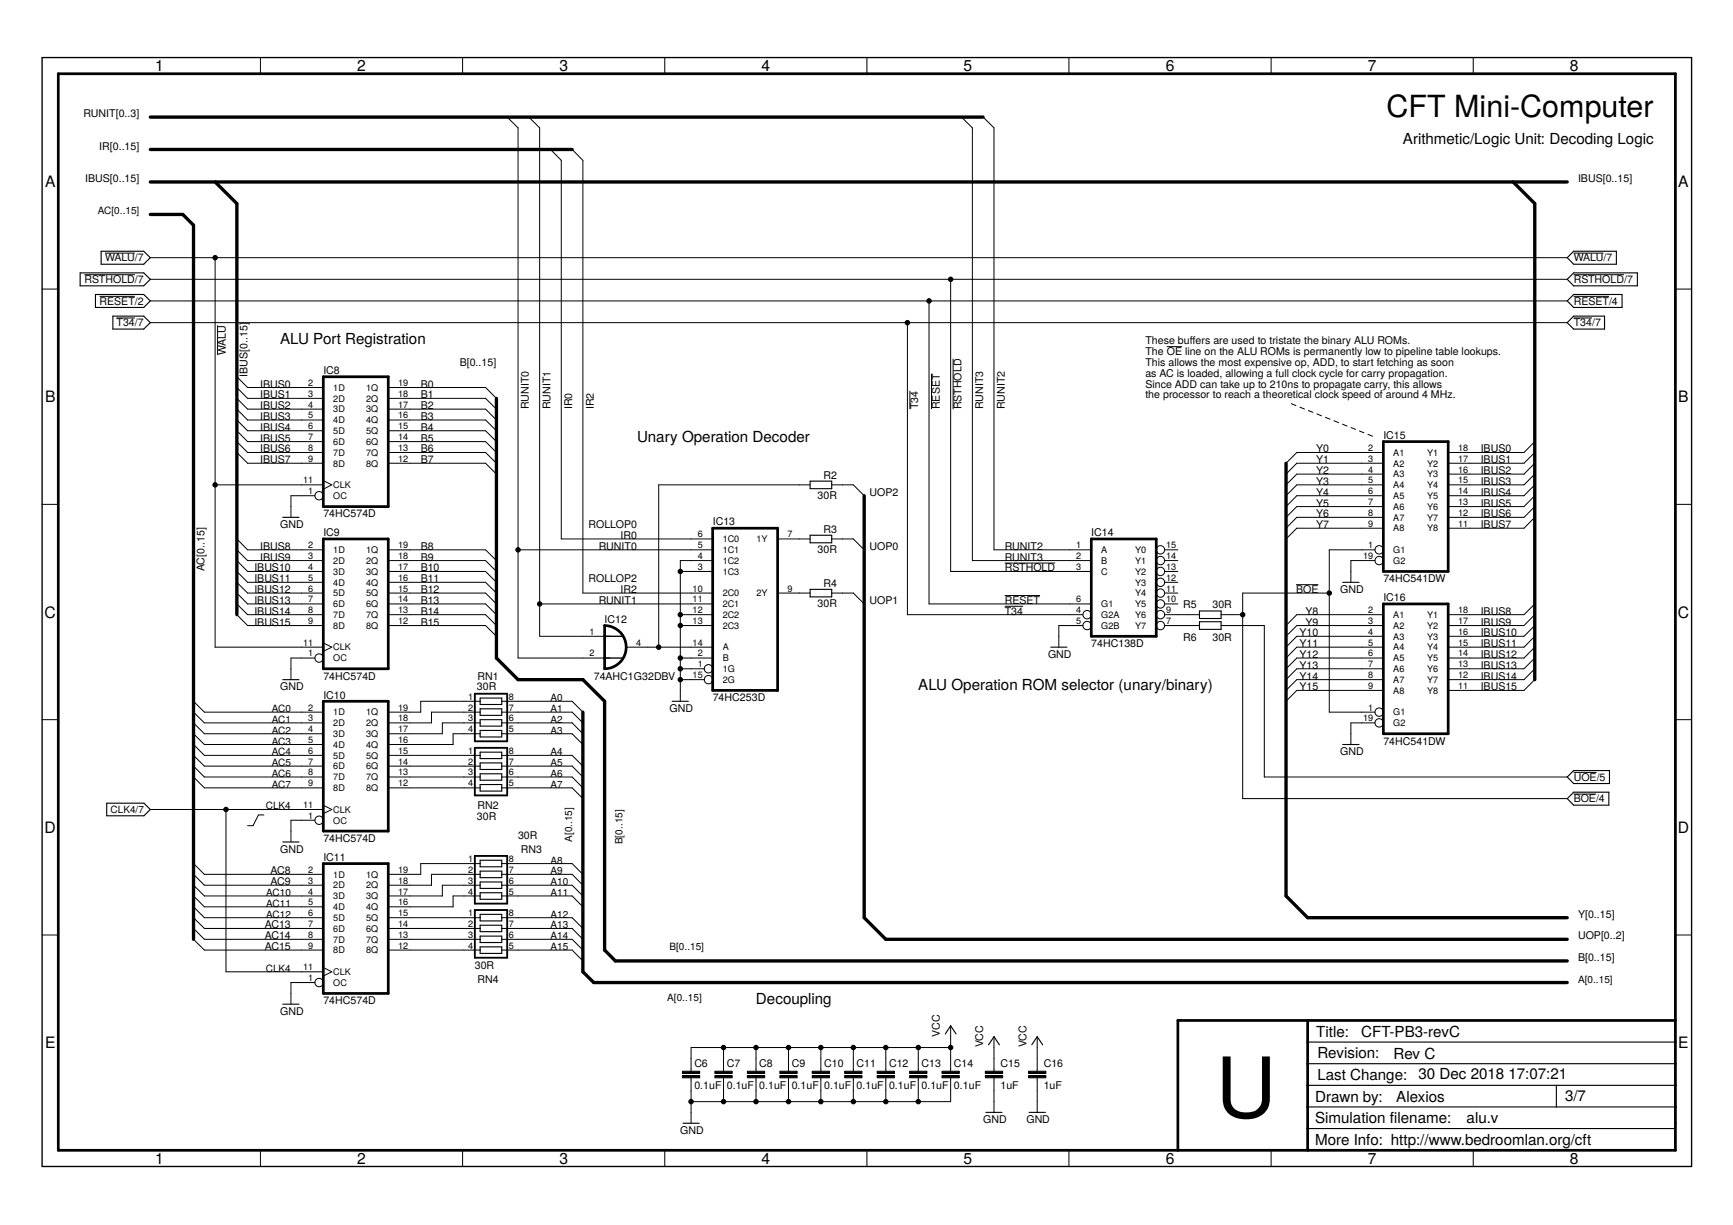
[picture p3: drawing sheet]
<svg xmlns="http://www.w3.org/2000/svg" width="297mm" height="210mm" viewBox="0 0 297 210" stroke-linecap="round" stroke-linejoin="round" font-family="sans-serif">
<defs><g id="words">
<text font-size="14.4" x="208.4" y="191.5">U</text>
<text font-size="5.2" x="237.6" y="20.1">CFT Mini-Computer</text>
<g font-size="2.7">
<text x="26.6" y="12.2">1</text>
<text x="61.2" y="12.2">2</text>
<text x="95.9" y="12.2">3</text>
<text x="130.5" y="12.2">4</text>
<text x="165.2" y="12.2">5</text>
<text x="199.8" y="12.2">6</text>
<text x="234.5" y="12.2">7</text>
<text x="269.1" y="12.2">8</text>
<text x="7.7" y="32">A</text>
<text x="287.7" y="32">A</text>
<text x="7.7" y="68.9">B</text>
<text x="287.7" y="68.9">B</text>
<text x="7.6" y="105.8">C</text>
<text x="287.6" y="105.8">C</text>
<text x="7.6" y="142.7">D</text>
<text x="287.6" y="142.7">D</text>
<text x="7.7" y="179.6">E</text>
<text x="287.7" y="179.6">E</text>
<text x="26.6" y="199.4">1</text>
<text x="61.2" y="199.4">2</text>
<text x="95.9" y="199.4">3</text>
<text x="130.5" y="199.4">4</text>
<text x="165.2" y="199.4">5</text>
<text x="199.8" y="199.4">6</text>
<text x="234.5" y="199.4">7</text>
<text x="269.1" y="199.4">8</text>
</g>
<g font-size="2.6">
<text x="240.5" y="24.7">Arithmetic/Logic Unit: Decoding Logic</text>
<text x="48" y="59">ALU Port Registration</text>
<text x="109.2" y="75.7">Unary Operation Decoder</text>
<text x="157.4" y="118.3">ALU Operation ROM selector (unary/binary)</text>
<text x="129.6" y="172.1">Decoupling</text>
<text x="225.6" y="177.6">Title:</text>
<text x="233.3" y="177.7">CFT-PB3-revC</text>
<text x="225.8" y="181.3">Revision:</text>
<text x="225.8" y="185">Last Change:</text>
<text x="238.9" y="181.4">Rev C</text>
<text x="243.1" y="185">30 Dec 2018</text>
<text x="258.6" y="185">17:07:21</text>
<text x="225.4" y="188.8">Drawn by:</text>
<text x="239.3" y="188.8">Alexios</text>
<text x="268.3" y="188.7">3/7</text>
<text x="225.4" y="192.5">Simulation flename:</text>
<text x="225.4" y="196.2">More Info: http://www.bedroomlan.org/cft</text>
<text x="238.2" y="192.5">i</text>
<text x="251.4" y="192.5">alu.v</text>
</g>
<g font-size="1.8">
<text x="14.3" y="20.1">RUNIT[0..3]</text>
<text x="17" y="25.6">IR[0..15]</text>
<text x="14.6" y="31.2">IBUS[0..15]</text>
<text x="270.5" y="31.2">IBUS[0..15]</text>
<text x="18" y="44.8">WALU/7</text>
<text x="269.7" y="44.8">WALU/7</text>
<text x="14.5" y="48.5">RSTHOLD/7</text>
<text x="17.1" y="52.2">RESET/2</text>
<text x="269.7" y="52.2">RESET/4</text>
<text x="269.7" y="48.5">RSTHOLD/7</text>
<text x="20" y="55.9">T34/7</text>
<text x="196.3" y="59">These bufers are used to tristate the binary ALU ROMs.</text>
<text x="203.9" y="59">f</text>
<text x="269.7" y="55.9">T34/7</text>
<text x="38.7" y="60.8" transform="rotate(-90 38.7 60.8)">WALU</text>
<text x="42.4" y="64.5" transform="rotate(-90 42.4 64.5)">IBUS[0..15]</text>
<text x="55.4" y="64.1">IC8</text>
<text x="78.8" y="62.7">B[0..15]</text>
<text x="196.3" y="60.8">The OE line on the ALU ROMs is permanently low to pipeline table lookups.</text>
<text x="196.3" y="62.7">This allows the most expensive op, ADD, to start fetching as soon</text>
<text x="196.3" y="64.5">as AC is loaded, allowing a full clock cycle for carry propagation.</text>
<text x="44.6" y="66.4">IBUS0</text>
<text x="44.6" y="68.3">IBUS1</text>
<text x="44.6" y="70.1">IBUS2</text>
<text x="44.6" y="72">IBUS3</text>
<text x="72.1" y="66.4">B0</text>
<text x="72.1" y="68.3">B1</text>
<text x="72.1" y="70.1">B2</text>
<text x="72.1" y="72">B3</text>
<text x="90.6" y="70.1" transform="rotate(-90 90.6 70.1)">RUNIT0</text>
<text x="94.4" y="70.1" transform="rotate(-90 94.4 70.1)">RUNIT1</text>
<text x="98.1" y="70.1" transform="rotate(-90 98.1 70.1)">IR0</text>
<text x="101.8" y="70.1" transform="rotate(-90 101.8 70.1)">IR2</text>
<text x="157.4" y="70.1" transform="rotate(-90 157.4 70.1)">T34</text>
<text x="161.1" y="70.1" transform="rotate(-90 161.1 70.1)">RESET</text>
<text x="164.8" y="70.1" transform="rotate(-90 164.8 70.1)">RSTHOLD</text>
<text x="168.5" y="70.1" transform="rotate(-90 168.5 70.1)">RUNIT3</text>
<text x="172.2" y="70.1" transform="rotate(-90 172.2 70.1)">RUNIT2</text>
<text x="196.3" y="66.4">Since ADD can take up to 210ns to propagate carry, this allows</text>
<text x="196.3" y="68.3">the processor to reach a theoretical clock speed of around 4 MHz.</text>
<text x="44.6" y="73.8">IBUS4</text>
<text x="44.6" y="75.7">IBUS5</text>
<text x="44.6" y="77.5">IBUS6</text>
<text x="72.1" y="73.8">B4</text>
<text x="72.1" y="75.7">B5</text>
<text x="72.1" y="77.5">B6</text>
<text x="225.6" y="77.5">Y0</text>
<text x="237.1" y="75.2">IC15</text>
<text x="253.8" y="77.5">IBUS0</text>
<text x="44.6" y="79.4">IBUS7</text>
<text x="72.1" y="79.4">B7</text>
<text x="141.2" y="82">R2</text>
<text x="225.6" y="79.4">Y1</text>
<text x="225.6" y="81.2">Y2</text>
<text x="225.6" y="83.1">Y3</text>
<text x="253.8" y="79.4">IBUS1</text>
<text x="253.8" y="81.2">IBUS2</text>
<text x="253.8" y="83.1">IBUS3</text>
<text x="55.4" y="88.6">74HC574D</text>
<text x="140.1" y="85.5">30R</text>
<text x="149" y="84.9">UOP2</text>
<text x="225.6" y="84.9">Y4</text>
<text x="225.6" y="86.8">Y5</text>
<text x="225.6" y="88.6">Y6</text>
<text x="253.8" y="84.9">IBUS4</text>
<text x="253.8" y="86.8">IBUS5</text>
<text x="253.8" y="88.6">IBUS6</text>
<text x="44.6" y="94.2">IBUS8</text>
<text x="48" y="90.5">GND</text>
<text x="55.4" y="91.9">IC9</text>
<text x="72.1" y="94.2">B8</text>
<text x="100.9" y="90.5">ROLLOP0</text>
<text x="102.6" y="94.2">RUNIT0</text>
<text x="106.3" y="92.4">IR0</text>
<text x="122.2" y="90">IC13</text>
<text x="140.1" y="94.8">30R</text>
<text x="141.2" y="91.3">R3</text>
<text x="149" y="94.2">UOP0</text>
<text x="172.2" y="94.2">RUNIT2</text>
<text x="187.1" y="91.9">IC14</text>
<text x="225.6" y="90.5">Y7</text>
<text x="253.8" y="90.5">IBUS7</text>
<text x="35" y="97.9" transform="rotate(-90 35 97.9)">AC[0..15]</text>
<text x="43.6" y="97.9">IBUS10</text>
<text x="43.6" y="99.8">IBUS11</text>
<text x="43.6" y="101.6">IBUS12</text>
<text x="44.6" y="96.1">IBUS9</text>
<text x="72.1" y="96.1">B9</text>
<text x="72.1" y="97.9">B10</text>
<text x="72.1" y="99.8">B11</text>
<text x="72.1" y="101.6">B12</text>
<text x="100.9" y="99.8">ROLLOP2</text>
<text x="106.3" y="101.6">IR2</text>
<text x="141.2" y="100.5">R4</text>
<text x="172.2" y="97.9">RSTHOLD</text>
<text x="172.2" y="96.1">RUNIT3</text>
<text x="222.2" y="101.6">BOE</text>
<text x="229.7" y="101.6">GND</text>
<text x="237.1" y="99.8">74HC541DW</text>
<text x="43.6" y="103.5">IBUS13</text>
<text x="43.6" y="105.3">IBUS14</text>
<text x="43.6" y="107.2">IBUS15</text>
<text x="72.1" y="103.5">B13</text>
<text x="72.1" y="105.3">B14</text>
<text x="72.1" y="107.2">B15</text>
<text x="102.6" y="103.5">RUNIT1</text>
<text x="103.6" y="106.7">IC12</text>
<text x="140.1" y="104">30R</text>
<text x="149" y="103.5">UOP1</text>
<text x="172.2" y="103.5">RESET</text>
<text x="172.2" y="105.3">T34</text>
<text x="202.8" y="104.2">R5</text>
<text x="207.8" y="104.2">30R</text>
<text x="223.8" y="105.3">Y8</text>
<text x="223.8" y="107.2">Y9</text>
<text x="237.1" y="103">IC16</text>
<text x="253.8" y="105.3">IBUS8</text>
<text x="253.8" y="107.2">IBUS9</text>
<text x="179.6" y="112.7">GND</text>
<text x="187.1" y="110.9">74HC138D</text>
<text x="202.8" y="109.8">R6</text>
<text x="207.8" y="109.8">30R</text>
<text x="222.7" y="109">Y10</text>
<text x="222.7" y="110.9">Y11</text>
<text x="222.7" y="112.7">Y12</text>
<text x="253.8" y="109">IBUS10</text>
<text x="253.8" y="110.9">IBUS11</text>
<text x="253.8" y="112.7">IBUS12</text>
<text x="48" y="118.3">GND</text>
<text x="55.4" y="116.5">74HC574D</text>
<text x="55.4" y="119.7">IC10</text>
<text x="81.7" y="118.3">30R</text>
<text x="81.8" y="116.5">RN1</text>
<text x="101.8" y="116.5">74AHC1G32DBV</text>
<text x="222.7" y="114.6">Y13</text>
<text x="222.7" y="116.5">Y14</text>
<text x="222.7" y="118.3">Y15</text>
<text x="253.8" y="114.6">IBUS13</text>
<text x="253.8" y="116.5">IBUS14</text>
<text x="253.8" y="118.3">IBUS15</text>
<text x="114.7" y="122">GND</text>
<text x="122.2" y="120.2">74HC253D</text>
<text x="229.7" y="129.4">GND</text>
<text x="237.1" y="127.6">74HC541DW</text>
<text x="269.7" y="133.8">UOE/5</text>
<text x="269.7" y="137.5">BOE/4</text>
<text x="81.7" y="140.5">30R</text>
<text x="81.8" y="138.7">RN2</text>
<text x="88.8" y="143.7">30R</text>
<text x="46.4" y="149.8">AC8</text>
<text x="48" y="146.1">GND</text>
<text x="55.4" y="144.3">74HC574D</text>
<text x="55.4" y="147.5">IC11</text>
<text x="89.3" y="146.1">RN3</text>
<text x="46.4" y="151.7">AC9</text>
<text x="45.4" y="159.1">AC13</text>
<text x="45.4" y="160.9">AC14</text>
<text x="270.5" y="160.9">UOP[0..2]</text>
<text x="270.5" y="157.2">Y[0..15]</text>
<text x="45.4" y="162.8">AC15</text>
<text x="81.4" y="166">30R</text>
<text x="270.5" y="164.7">B[0..15]</text>
<text x="48" y="173.9">GND</text>
<text x="55.4" y="172.1">74HC574D</text>
<text x="81.8" y="168.4">RN4</text>
<text x="161.1" y="177.6" transform="rotate(-90 161.1 177.6)">VCC</text>
<text x="168.5" y="179.5" transform="rotate(-90 168.5 179.5)">VCC</text>
<text x="175.9" y="179.5" transform="rotate(-90 175.9 179.5)">VCC</text>
<text x="119" y="182.9">C6</text>
<text x="124.6" y="182.9">C7</text>
<text x="130.1" y="182.9">C8</text>
<text x="135.7" y="182.9">C9</text>
<text x="141.3" y="182.9">C10</text>
<text x="146.8" y="182.9">C11</text>
<text x="152.4" y="182.9">C12</text>
<text x="157.9" y="182.9">C13</text>
<text x="163.5" y="182.9">C14</text>
<text x="171.5" y="182.9">C15</text>
<text x="178.9" y="182.9">C16</text>
<text x="119" y="186.6">0.1uF 0.1uF 0.1uF 0.1uF 0.1uF 0.1uF 0.1uF 0.1uF 0.1uF</text>
<text x="171.5" y="186.6">1uF</text>
<text x="178.9" y="186.6">1uF</text>
<text x="116.6" y="194.3">GND</text>
<text x="168.5" y="192.5">GND</text>
<text x="175.9" y="192.5">GND</text>
</g>
<g font-size="1.7">
<text x="16.8" y="36.7">AC[0..15]</text>
<text x="46.6" y="122">AC0</text>
<text x="46.6" y="123.9">AC1</text>
<text x="46.6" y="125.7">AC2</text>
<text x="94.4" y="125.7">A3</text>
<text x="94.4" y="123.9">A2</text>
<text x="94.4" y="122">A1</text>
<text x="94.4" y="120.2">A0</text>
<text x="46.6" y="127.6">AC3</text>
<text x="46.6" y="129.4">AC4</text>
<text x="46.6" y="131.3">AC5</text>
<text x="94.4" y="131.3">A5</text>
<text x="94.4" y="129.4">A4</text>
<text x="46.6" y="133.1">AC6</text>
<text x="46.6" y="135">AC7</text>
<text x="94.4" y="135">A7</text>
<text x="94.4" y="133.1">A6</text>
<text x="19" y="139.3">CLK4/7</text>
<text x="45.6" y="138.7">CLK4</text>
<text x="94.4" y="149.8">A9</text>
<text x="94.4" y="148">A8</text>
<text x="98.1" y="144.3" transform="rotate(-90 98.1 144.3)">A[0..15]</text>
<text x="106.7" y="144.6" transform="rotate(-90 106.7 144.6)">B[0..15]</text>
<text x="45.6" y="153.5">AC10</text>
<text x="45.6" y="155.4">AC11</text>
<text x="94.4" y="153.5">A11</text>
<text x="94.4" y="151.7">A10</text>
<text x="45.6" y="157.2">AC12</text>
<text x="94.4" y="160.9">A14</text>
<text x="94.4" y="159.1">A13</text>
<text x="94.4" y="157.2">A12</text>
<text x="45.6" y="166.5">CLK4</text>
<text x="94.4" y="162.8">A15</text>
<text x="114.7" y="162.8">B[0..15]</text>
<text x="114.4" y="171.4">A[0..15]</text>
<text x="270.5" y="168.4">A[0..15]</text>
</g>
<g font-size="1.6">
<text x="52.8" y="66.1">2</text>
<text x="52.8" y="68">3</text>
<text x="52.8" y="69.9">4</text>
<text x="52.8" y="71.7">5</text>
<text x="57.1" y="67">1D</text>
<text x="57.1" y="68.8">2D</text>
<text x="57.1" y="70.7">3D</text>
<text x="62.7" y="70.7">3Q</text>
<text x="62.7" y="68.8">2Q</text>
<text x="62.7" y="67">1Q</text>
<text x="68.2" y="71.7">16</text>
<text x="68.2" y="69.9">17</text>
<text x="68.2" y="68">18</text>
<text x="68.2" y="66.1">19</text>
<text x="52.8" y="73.6">6</text>
<text x="52.8" y="75.4">7</text>
<text x="52.8" y="77.3">8</text>
<text x="57.1" y="72.5">4D</text>
<text x="57.1" y="74.4">5D</text>
<text x="57.1" y="76.2">6D</text>
<text x="62.7" y="76.2">6Q</text>
<text x="62.7" y="74.4">5Q</text>
<text x="62.7" y="72.5">4Q</text>
<text x="68.2" y="77.3">13</text>
<text x="68.2" y="75.4">14</text>
<text x="68.2" y="73.6">15</text>
<text x="234.5" y="77.3">2</text>
<text x="249.9" y="77.3">18</text>
<text x="52" y="82.8">11</text>
<text x="52.8" y="79.1">9</text>
<text x="57.1" y="78.1">7D</text>
<text x="57.1" y="79.9">8D</text>
<text x="57.1" y="83.6">CLK</text>
<text x="62.7" y="79.9">8Q</text>
<text x="62.7" y="78.1">7Q</text>
<text x="68.2" y="79.1">12</text>
<text x="234.5" y="79.1">3</text>
<text x="234.5" y="81">4</text>
<text x="234.5" y="82.8">5</text>
<text x="238.8" y="78.1">A1</text>
<text x="238.8" y="79.9">A2</text>
<text x="238.8" y="81.8">A3</text>
<text x="238.8" y="83.6">A4</text>
<text x="244.6" y="83.7">Y4</text>
<text x="244.6" y="81.8">Y3</text>
<text x="244.6" y="79.9">Y2</text>
<text x="244.6" y="78.1">Y1</text>
<text x="249.9" y="82.8">15</text>
<text x="249.9" y="81">16</text>
<text x="249.9" y="79.1">17</text>
<text x="52.8" y="84.7">1</text>
<text x="57.1" y="85.5">OC</text>
<text x="234.5" y="84.7">6</text>
<text x="234.5" y="86.5">7</text>
<text x="234.5" y="88.4">8</text>
<text x="238.8" y="85.5">A5</text>
<text x="238.8" y="87.4">A6</text>
<text x="238.8" y="89.2">A7</text>
<text x="244.6" y="89.2">Y7</text>
<text x="244.6" y="87.4">Y6</text>
<text x="244.6" y="85.5">Y5</text>
<text x="249.9" y="88.4">12</text>
<text x="249.9" y="86.5">13</text>
<text x="249.9" y="84.7">14</text>
<text x="52.8" y="93.9">2</text>
<text x="52.8" y="95.8">3</text>
<text x="57.1" y="94.8">1D</text>
<text x="62.7" y="94.8">1Q</text>
<text x="68.2" y="95.8">18</text>
<text x="68.2" y="93.9">19</text>
<text x="119.6" y="95.8">4</text>
<text x="119.6" y="93.9">5</text>
<text x="119.6" y="92.1">6</text>
<text x="123.9" y="94.8">1C1</text>
<text x="123.9" y="92.9">1C0</text>
<text x="129.7" y="92.9">1Y</text>
<text x="135" y="92.1">7</text>
<text x="184.5" y="93.9">1</text>
<text x="184.5" y="95.8">2</text>
<text x="188.8" y="94.8">A</text>
<text x="194.6" y="94.8">Y0</text>
<text x="199.9" y="95.8">14</text>
<text x="199.9" y="93.9">15</text>
<text x="233.7" y="95.8">19</text>
<text x="234.5" y="93.9">1</text>
<text x="234.5" y="90.2">9</text>
<text x="238.8" y="94.8">G1</text>
<text x="238.8" y="91.1">A8</text>
<text x="244.6" y="91.1">Y8</text>
<text x="249.9" y="90.2">11</text>
<text x="52.8" y="97.7">4</text>
<text x="52.8" y="99.5">5</text>
<text x="52.8" y="101.4">6</text>
<text x="57.1" y="96.6">2D</text>
<text x="57.1" y="98.5">3D</text>
<text x="57.1" y="100.3">4D</text>
<text x="62.7" y="100.3">4Q</text>
<text x="62.7" y="98.5">3Q</text>
<text x="62.7" y="96.6">2Q</text>
<text x="68.2" y="101.4">15</text>
<text x="68.2" y="99.5">16</text>
<text x="68.2" y="97.7">17</text>
<text x="118.7" y="101.4">10</text>
<text x="119.6" y="97.7">3</text>
<text x="123.9" y="98.5">1C3</text>
<text x="123.9" y="96.6">1C2</text>
<text x="135" y="101.4">9</text>
<text x="184.5" y="97.7">3</text>
<text x="188.8" y="96.6">B</text>
<text x="188.8" y="98.5">C</text>
<text x="194.6" y="100.3">Y3</text>
<text x="194.6" y="98.5">Y2</text>
<text x="194.6" y="96.6">Y1</text>
<text x="199.9" y="101.4">11</text>
<text x="199.9" y="99.5">12</text>
<text x="199.9" y="97.7">13</text>
<text x="238.8" y="96.6">G2</text>
<text x="52.8" y="103.2">7</text>
<text x="52.8" y="105.1">8</text>
<text x="52.8" y="106.9">9</text>
<text x="57.1" y="102.2">5D</text>
<text x="57.1" y="104">6D</text>
<text x="57.1" y="105.9">7D</text>
<text x="57.1" y="107.7">8D</text>
<text x="62.7" y="107.8">8Q</text>
<text x="62.7" y="105.9">7Q</text>
<text x="62.7" y="104">6Q</text>
<text x="62.7" y="102.2">5Q</text>
<text x="68.2" y="106.9">12</text>
<text x="68.2" y="105.1">13</text>
<text x="68.2" y="103.2">14</text>
<text x="118.7" y="103.2">11</text>
<text x="118.7" y="105.1">12</text>
<text x="118.7" y="106.9">13</text>
<text x="123.9" y="102.2">2C0</text>
<text x="123.9" y="104">2C1</text>
<text x="123.9" y="105.9">2C2</text>
<text x="123.9" y="107.7">2C3</text>
<text x="129.7" y="102.2">2Y</text>
<text x="184.5" y="105.1">4</text>
<text x="184.5" y="106.9">5</text>
<text x="184.5" y="103.2">6</text>
<text x="188.8" y="105.9">G2A</text>
<text x="188.8" y="107.7">G2B</text>
<text x="188.8" y="104">G1</text>
<text x="194.6" y="107.8">Y7</text>
<text x="194.6" y="105.9">Y6</text>
<text x="194.6" y="104">Y5</text>
<text x="194.6" y="102.2">Y4</text>
<text x="199.9" y="106.9">7</text>
<text x="199.9" y="105.1">9</text>
<text x="199.9" y="103.2">10</text>
<text x="234.5" y="105.1">2</text>
<text x="234.5" y="106.9">3</text>
<text x="238.8" y="105.9">A1</text>
<text x="238.8" y="107.7">A2</text>
<text x="244.6" y="107.8">Y2</text>
<text x="244.6" y="105.9">Y1</text>
<text x="249.9" y="106.9">17</text>
<text x="249.9" y="105.1">18</text>
<text x="52" y="110.6">11</text>
<text x="52.8" y="112.5">1</text>
<text x="57.1" y="113.3">OC</text>
<text x="57.1" y="111.4">CLK</text>
<text x="101" y="108.8">1</text>
<text x="101" y="112.5">2</text>
<text x="109" y="110.6">4</text>
<text x="118.7" y="110.6">14</text>
<text x="119.6" y="112.5">2</text>
<text x="123.9" y="113.3">B</text>
<text x="123.9" y="111.4">A</text>
<text x="234.5" y="108.8">4</text>
<text x="234.5" y="110.6">5</text>
<text x="234.5" y="112.5">6</text>
<text x="238.8" y="109.6">A3</text>
<text x="238.8" y="111.4">A4</text>
<text x="238.8" y="113.3">A5</text>
<text x="244.6" y="113.3">Y5</text>
<text x="244.6" y="111.5">Y4</text>
<text x="244.6" y="109.6">Y3</text>
<text x="249.9" y="112.5">14</text>
<text x="249.9" y="110.6">15</text>
<text x="249.9" y="108.8">16</text>
<text x="80.2" y="119.9">1</text>
<text x="87.2" y="119.9">8</text>
<text x="118.7" y="116.2">15</text>
<text x="119.6" y="114.3">1</text>
<text x="123.9" y="115.2">1G</text>
<text x="123.9" y="117">2G</text>
<text x="234.5" y="114.3">7</text>
<text x="234.5" y="116.2">8</text>
<text x="234.5" y="118">9</text>
<text x="238.8" y="115.2">A6</text>
<text x="238.8" y="117">A7</text>
<text x="238.8" y="118.9">A8</text>
<text x="244.6" y="118.9">Y8</text>
<text x="244.6" y="117">Y7</text>
<text x="244.6" y="115.2">Y6</text>
<text x="249.9" y="118">11</text>
<text x="249.9" y="116.2">12</text>
<text x="249.9" y="114.3">13</text>
<text x="52.8" y="121.8">2</text>
<text x="52.8" y="123.6">3</text>
<text x="52.8" y="125.5">4</text>
<text x="57.1" y="122.6">1D</text>
<text x="57.1" y="124.4">2D</text>
<text x="62.7" y="124.4">2Q</text>
<text x="62.7" y="122.6">1Q</text>
<text x="68.2" y="125.5">17</text>
<text x="68.2" y="123.6">18</text>
<text x="68.2" y="121.8">19</text>
<text x="80.2" y="121.8">2</text>
<text x="80.2" y="123.6">3</text>
<text x="80.2" y="125.5">4</text>
<text x="87.2" y="125.5">5</text>
<text x="87.2" y="123.6">6</text>
<text x="87.2" y="121.8">7</text>
<text x="233.7" y="123.6">19</text>
<text x="234.5" y="121.8">1</text>
<text x="238.8" y="122.6">G1</text>
<text x="238.8" y="124.4">G2</text>
<text x="52.8" y="127.3">5</text>
<text x="52.8" y="129.2">6</text>
<text x="52.8" y="131">7</text>
<text x="57.1" y="126.3">3D</text>
<text x="57.1" y="128.1">4D</text>
<text x="57.1" y="130">5D</text>
<text x="57.1" y="131.8">6D</text>
<text x="62.7" y="131.9">6Q</text>
<text x="62.7" y="130">5Q</text>
<text x="62.7" y="128.1">4Q</text>
<text x="62.7" y="126.3">3Q</text>
<text x="68.2" y="131">14</text>
<text x="68.2" y="129.2">15</text>
<text x="68.2" y="127.3">16</text>
<text x="80.2" y="131">2</text>
<text x="80.2" y="129.2">1</text>
<text x="87.2" y="131">7</text>
<text x="87.2" y="129.2">8</text>
<text x="52.8" y="132.9">8</text>
<text x="52.8" y="134.7">9</text>
<text x="57.1" y="133.7">7D</text>
<text x="57.1" y="135.5">8D</text>
<text x="62.7" y="135.6">8Q</text>
<text x="62.7" y="133.7">7Q</text>
<text x="68.2" y="134.7">12</text>
<text x="68.2" y="132.9">13</text>
<text x="80.2" y="132.9">3</text>
<text x="80.2" y="134.7">4</text>
<text x="87.2" y="134.7">5</text>
<text x="87.2" y="132.9">6</text>
<text x="52" y="138.4">11</text>
<text x="52.8" y="140.3">1</text>
<text x="57.1" y="141.1">OC</text>
<text x="57.1" y="139.3">CLK</text>
<text x="52.8" y="149.6">2</text>
<text x="68.2" y="149.6">19</text>
<text x="80.2" y="149.6">2</text>
<text x="80.2" y="147.7">1</text>
<text x="87.2" y="149.6">7</text>
<text x="87.2" y="147.7">8</text>
<text x="52.8" y="151.4">3</text>
<text x="52.8" y="153.3">4</text>
<text x="52.8" y="155.1">5</text>
<text x="57.1" y="150.4">1D</text>
<text x="57.1" y="152.2">2D</text>
<text x="57.1" y="154.1">3D</text>
<text x="57.1" y="155.9">4D</text>
<text x="62.7" y="156">4Q</text>
<text x="62.7" y="154.1">3Q</text>
<text x="62.7" y="152.2">2Q</text>
<text x="62.7" y="150.4">1Q</text>
<text x="68.2" y="155.1">16</text>
<text x="68.2" y="153.3">17</text>
<text x="68.2" y="151.4">18</text>
<text x="80.2" y="151.4">3</text>
<text x="80.2" y="153.3">4</text>
<text x="87.2" y="153.3">5</text>
<text x="87.2" y="151.4">6</text>
<text x="52.8" y="157">6</text>
<text x="52.8" y="158.8">7</text>
<text x="52.8" y="160.7">8</text>
<text x="57.1" y="157.8">5D</text>
<text x="57.1" y="159.6">6D</text>
<text x="57.1" y="161.5">7D</text>
<text x="62.7" y="161.5">7Q</text>
<text x="62.7" y="159.7">6Q</text>
<text x="62.7" y="157.8">5Q</text>
<text x="68.2" y="160.7">13</text>
<text x="68.2" y="158.8">14</text>
<text x="68.2" y="157">15</text>
<text x="80.2" y="158.8">2</text>
<text x="80.2" y="160.7">3</text>
<text x="80.2" y="157">1</text>
<text x="87.2" y="160.7">6</text>
<text x="87.2" y="158.8">7</text>
<text x="87.2" y="157">8</text>
<text x="52" y="166.2">11</text>
<text x="52.8" y="162.5">9</text>
<text x="57.1" y="163.4">8D</text>
<text x="57.1" y="167.1">CLK</text>
<text x="62.7" y="163.4">8Q</text>
<text x="68.2" y="162.5">12</text>
<text x="80.2" y="162.5">4</text>
<text x="87.2" y="162.5">5</text>
<text x="52.8" y="168.1">1</text>
<text x="57.1" y="168.9">OC</text>
</g>
</g></defs>
<g fill="none" stroke="#000" stroke-width=".17">
<path d="M10 12.6h277.2v184.5h-277.2zM44.6 9.9v2.7M79.3 9.9v2.7M113.9 9.9v2.7M148.6 9.9v2.7M183.2 9.9v2.7M217.9 9.9v2.7M252.5 9.9v2.7M86.9 20.1l1.9 1.8v90.9h15.7M90.6 20.1l1.9 1.8v87.1h12M94.4 25.6l1.8 1.9v64.9h26M98.1 25.6l1.8 1.9v74.1h22.3"/>
<path d="M164.8 20.1l1.9 1.8v74.2h20.3M168.5 20.1l1.9 1.8v72.3h16.6M7.2 49.5h2.8M14.5 47.1h8.6M17.1 50.8h6M18 43.4h5.1M20 54.5h3.1M25.8 51.6h242.8M25.8 47.9h242.8M25.8 44.2h242.8M25.8 55.3h242.8M36.9 44.2v66.7h18.5"/>
<path d="M37.3 55.7v5.1M155.5 55.3v50h30.1M159.2 51.6v51.9h27.8M162.9 47.9v50h24.1M200 59.4h2.6M269.7 50.8h6.1M269.7 47.1h8.7M269.7 43.4h5.1M269.7 54.5h3.2M287.2 49.5h2.7M40.6 64.6l1.8 1.8h13M40.6 66.4l1.8 1.9h13"/>
<path d="M40.6 68.3l1.8 1.8h13M40.6 70.1l1.8 1.9h13M40.6 72l1.8 1.8h13M40.6 73.8l1.8 1.9h13M40.6 75.7l1.8 1.8h13M40.6 77.5l1.8 1.9h13M66.5 66.4h16.7l1.9 1.9M66.5 68.3h16.7l1.9 1.8M66.5 70.1h16.7l1.9 1.9M66.5 72h16.7l1.9 1.8M66.5 73.8h16.7l1.9 1.9M66.5 75.7h16.7l1.9 1.8"/>
<path d="M66.5 77.5h16.7l1.9 1.9M66.5 79.4h16.7l1.9 1.8M156 67v3.1M159.7 64.1v6M163.4 61.5v8.6M221.3 69.2l.8 .3M222.8 69.8l.8 .3M224.3 70.4l.7 .3M225.7 70.9l.8 .3M227.2 71.5l.8 .3M228.6 72.1l.8 .3M230.1 72.7l.8 .3"/>
<path d="M231.6 73.3l.7 .3M233 73.9l.8 .3M234.5 74.4l.7 .3M237.1 77.5h-14.8l-1.9 1.9M237.1 79.4h-14.8l-1.9 1.8M263.1 75.7l-1.9 1.8h-13M263.1 77.5l-1.9 1.9h-13M263.1 79.4l-1.9 1.8h-13M7.2 86.4h2.8M36.9 83.1h18.5M40.6 92.4l1.8 1.8h13M40.6 94.2l1.8 1.9h13"/>
<path d="M40.6 96.1l1.8 1.8h13M40.6 99.8l1.8 1.8h13M40.6 97.9l1.8 1.9h13M54 84.9h-4.1v3.7M55.4 82.4l1.5 .7-1.5 .7M66.5 94.2h16.7l1.9 1.9M66.5 96.1h16.7l1.9 1.8M66.5 97.9h16.7l1.9 1.9M66.5 99.8h16.7l1.9 1.8M88.8 94.2h33.4M116.6 97.9h5.6M122.2 96.1h-5.6v24.1"/>
<path d="M133.3 92.4h5.6M138.9 83.1h-26v27.8M142.6 83.1h3.7l1.8 1.8M142.6 92.4h3.7l1.8 1.8M172.2 96.5h8.6M199.6 94.2h2.3M199.6 96.1h2.3M199.6 97.9h2.3M199.6 99.8h2.3M235.7 94.2h-7.9v27.8h7.9M235.7 96.1h-4.2v3.7M237.1 84.9h-14.8l-1.9 1.9"/>
<path d="M237.1 83.1h-14.8l-1.9 1.8M237.1 81.2h-14.8l-1.9 1.9M237.1 86.8h-14.8l-1.9 1.8M237.1 88.6h-14.8l-1.9 1.9M237.1 90.5h-14.8l-1.9 1.9M263.1 83.1l-1.9 1.8h-13M263.1 81.2l-1.9 1.9h-13M263.1 84.9l-1.9 1.9h-13M263.1 86.8l-1.9 1.8h-13M263.1 88.6l-1.9 1.9h-13M287.2 86.4h2.7M40.6 103.5l1.8 1.8h13"/>
<path d="M40.6 105.3l1.8 1.9h13M40.6 101.6l1.8 1.9h13M54 112.8h-4.1v3.7M55.4 110.2l1.5 .7-1.5 .7M66.5 105.3h16.7l1.9 1.9M66.5 107.2h16.7l1.9 1.8M66.5 103.5h16.7l1.9 1.8M66.5 101.6h16.7l1.9 1.9M92.5 103.5h29.7M107.3 110.9h14.9M116.6 105.3h5.6M116.6 107.2h5.6"/>
<path d="M116.6 114.6h4.1M116.6 112.8h5.6M116.6 116.5h4.1M133.3 101.6h5.6M142.6 101.6h3.7l1.8 1.9M172.2 102h6.1M172.2 103.9h3.2M185.6 107.2h-4.1v3.7M199.6 105.3h6M199.6 107.2h6M199.6 103.5h2.3M199.6 101.6h2.3"/>
<path d="M209.3 105.3h3.7M209.3 107.2h7.4v25.9h51.9M222.1 100.2h3.9M227.8 101.6h-14.8v35.2h55.6M237.1 105.3h-14.8l-1.9 1.9M237.1 107.2h-14.8l-1.9 1.8M237.1 114.6h-14.8l-1.9 1.9M237.1 112.8h-14.8l-1.9 1.8M237.1 110.9h-14.8l-1.9 1.9M237.1 116.5h-14.8l-1.9 1.8M237.1 109h-14.8l-1.9 1.9M237.1 118.3h-14.8l-1.9 1.9"/>
<path d="M263.1 103.5l-1.9 1.8h-13M263.1 105.3l-1.9 1.9h-13M263.1 112.8l-1.9 1.8h-13M263.1 110.9l-1.9 1.9h-13M263.1 109l-1.9 1.9h-13M263.1 114.6l-1.9 1.9h-13M263.1 107.2l-1.9 1.8h-13M263.1 116.5l-1.9 1.8h-13M7.2 123.3h2.8M25.8 138.7h29.6M33.2 120.2l1.8 1.8h20.4M33.2 122l1.8 1.9h20.4"/>
<path d="M33.2 123.9l1.8 1.8h20.4M33.2 125.7l1.8 1.9h20.4M33.2 127.6l1.8 1.8h20.4M33.2 129.4l1.8 1.9h20.4M33.2 131.3l1.8 1.8h20.4M33.2 133.1l1.8 1.9h20.4M38.7 138.7v27.8h16.7M45.2 139.6h-.9l-.9 1.9h-1M55.4 138l1.5 .7-1.5 .7M66.5 129.4h15.8M66.5 131.3h15.8M66.5 133.1h15.8"/>
<path d="M66.5 135h15.8M82.3 120.2h-10.2v1.8h-5.6M82.3 122h-8.3v1.9h-7.5M82.3 123.9h-6.5v1.8h-9.3M82.3 125.7h-4.6v1.9h-11.2M86 122h12.1l1.8 1.9M86 123.9h12.1l1.8 1.8M86 125.7h12.1l1.8 1.9M86 129.4h12.1l1.8 1.9M86 131.3h12.1l1.8 1.8M86 133.1h12.1l1.8 1.9M86 135h12.1l1.8 1.8"/>
<path d="M86 120.2h12.1l1.8 1.8M235.7 123.9h-4.2v3.7M269.7 132.4h4M269.7 136.1h3.9M287.2 123.3h2.7M33.2 148l1.8 1.8h20.4M33.2 149.8l1.8 1.9h20.4M33.2 151.7l1.8 1.8h20.4M33.2 153.5l1.8 1.9h20.4M33.2 155.4l1.8 1.8h20.4M33.2 157.2l1.8 1.9h20.4M33.2 159.1l1.8 1.9h20.4"/>
<path d="M54 140.5h-4.1v3.8M66.5 157.2h15.8M66.5 159.1h15.8M82.3 148h-10.2v1.8h-5.6M82.3 149.8h-8.3v1.9h-7.5M82.3 151.7h-6.5v1.8h-9.3M82.3 153.5h-4.6v1.9h-11.2M86 149.8h12.1l1.8 1.9M86 151.7h12.1l1.8 1.8M86 153.5h12.1l1.8 1.9M86 157.2h12.1l1.8 1.9M86 159.1h12.1l1.8 1.9"/>
<path d="M86 148h12.1l1.8 1.8M7.2 160.2h2.8M33.2 161l1.8 1.8h20.4M54 168.4h-4.1v3.7M55.4 165.8l1.5 .7-1.5 .7M66.5 161h15.8M66.5 162.8h15.8M86 161h12.1l1.8 1.8M86 162.8h12.1l1.8 1.9M124 179.5v4.1M129.6 179.5v4.1M135.1 179.5v4.1"/>
<path d="M140.7 179.5v4.1M146.3 179.5v4.1M151.8 179.5v4.1M157.4 179.5v4.1M162.9 175.8v7.8M162.9 179.5h-44.5v4.1M170.4 177.6v6M177.8 177.6v6M287.2 160.2h2.7M44.6 197.1v2.8M79.3 197.1v2.8M113.9 197.1v2.8"/>
<path d="M118.4 184.7v7.8M124 184.7v4.1M129.6 184.7v4.1M135.1 184.7v4.1M140.7 184.7v4.1M146.3 184.7v4.1M148.6 197.1v2.8M151.8 184.7v4.1M157.4 184.7v4.1M162.9 184.7v4.1h-44.5M170.4 184.7v5.9M177.8 184.7v5.9"/>
<path d="M183.2 197.1v2.8M217.9 197.1v2.8M252.5 197.1v2.8M287.2 197h.1"/>
<circle cx="54.7" cy="84.9" r=".72"/>
<circle cx="198.9" cy="96.1" r=".72"/>
<circle cx="198.9" cy="99.8" r=".72"/>
<circle cx="198.9" cy="94.2" r=".72"/>
<circle cx="198.9" cy="97.9" r=".72"/>
<circle cx="236.4" cy="94.2" r=".72"/>
<circle cx="236.4" cy="96.1" r=".72"/>
<circle cx="54.7" cy="112.8" r=".72"/>
<circle cx="121.4" cy="114.6" r=".72"/>
<circle cx="121.4" cy="116.5" r=".72"/>
<circle cx="186.3" cy="105.3" r=".72"/>
<circle cx="186.3" cy="107.2" r=".72"/>
<circle cx="198.9" cy="101.6" r=".72"/>
<circle cx="198.9" cy="103.5" r=".72"/>
<circle cx="198.9" cy="107.2" r=".72"/>
<circle cx="198.9" cy="105.3" r=".72"/>
<circle cx="236.4" cy="123.9" r=".72"/>
<circle cx="236.4" cy="122" r=".72"/>
<circle cx="54.7" cy="140.5" r=".72"/>
<circle cx="54.7" cy="168.4" r=".72"/>
</g>
<g fill="none" stroke="#000" stroke-width=".19">
<path d="M13.7 46.8h10.9l1.2 1.1-1.2 1.1h-10.9zM16.4 50.5h8.2l1.2 1.1-1.2 1.1h-8.2zM17.3 43.1h7.3l1.2 1.1-1.2 1.1h-7.3zM19.3 54.2h5.3l1.2 1.1-1.2 1.1h-5.3zM268.6 51.6l1.1-1.1h8.3v2.2h-8.3zM268.6 44.2l1.1-1.1h7.4v2.2h-7.4zM269.7 46.8h10.9v2.2h-10.9l-1.1-1.1zM269.7 54.2h5.3v2.2h-5.3l-1.1-1.1zM48.5 88.6h2.7M138.9 82.4h3.7v1.3h-3.7zM138.9 91.7h3.7v1.3h-3.7zM230.1 99.8h2.8"/>
<path d="M48.5 116.5h2.7M82.3 119.6h3.7v1.1h-3.7zM138.9 101h3.7v1.3h-3.7zM180.1 110.9h2.8M205.6 104.7h3.7v1.3h-3.7zM205.6 106.5h3.7v1.3h-3.7zM18.3 137.6h6.4l1.1 1.1-1.1 1.1h-6.4zM82.3 121.5h3.7v1.1h-3.7zM82.3 123.3h3.7v1.1h-3.7zM82.3 125.2h3.7v1.1h-3.7zM82.3 128.9h3.7v1.1h-3.7zM82.3 130.7h3.7v1.1h-3.7z"/>
<path d="M82.3 132.6h3.7v1.1h-3.7zM82.3 134.4h3.7v1.2h-3.7zM115.2 120.2h2.8M230.1 127.6h2.8M268.6 133.1l1.1-1.1h6.2v2.3h-6.2zM269.7 135.7h6.1v2.3h-6.1l-1.1-1.2zM48.5 144.3h2.7M82.3 147.4h3.7v1.1h-3.7zM82.3 149.3h3.7v1.1h-3.7zM82.3 151.1h3.7v1.1h-3.7zM82.3 153h3.7v1.1h-3.7zM82.3 156.7h3.7v1.1h-3.7z"/>
<path d="M82.3 158.5h3.7v1.1h-3.7zM48.5 172.1h2.7M82.3 160.4h3.7v1.1h-3.7zM82.3 162.2h3.7v1.2h-3.7zM162 177.2l.9-1.4 1 1.4M169.4 179l1-1.4 .9 1.4M176.8 179l1-1.4 .9 1.4M224.1 178.6h63.1M117.1 192.5h2.7M169 190.6h2.7M176.4 190.6h2.8M224.1 182.3h63.1"/>
<path d="M224.1 186h63.1M224.1 189.7h63.1M266.8 186v3.7M287.2 192.5v.9h-63.1"/>
</g>
<path d="M10 12.6h277.2v184.5h-277.2zM55.4 64.6h11.1v22.2h-11.1zM237.1 75.7h11.1v22.2h-11.1zM55.4 92.4h11.1v22.2h-11.1zM122.2 90.5h11.1v27.8h-11.1zM187 92.4h11.2v16.6h-11.2zM103.6 107.2a3.7 3.7 0 0 1 3.7 3.7 3.7 3.7 0 0 1-3.7 3.7zM237.1 103.5h11.1v22.2h-11.1zM55.4 120.2h11.1v22.2h-11.1zM55.4 148h11.1v22.2h-11.1zM224.1 174.9v22.2M287.2 174.9h-85.3v22.2" fill="none" stroke="#000" stroke-width=".47"/>
<path d="M7.2 9.9h282.7v190h-282.7zM103.6 109h3.2M103.6 112.8h3.2" fill="none" stroke="#000" stroke-width=".23"/>
<g fill="#000" stroke="#000" stroke-width=".17">
<path d="M117 183.6h2.9v.3h-2.9zM117 184.3h2.9v.4h-2.9zM122.5 183.6h3v.3h-3zM122.5 184.3h3v.4h-3zM128.1 183.6h3v.3h-3zM128.1 184.3h3v.4h-3zM133.7 183.6h2.9v.3h-2.9zM133.7 184.3h2.9v.4h-2.9zM139.2 183.6h3v.3h-3zM139.2 184.3h3v.4h-3zM144.8 183.6h2.9v.3h-2.9zM144.8 184.3h2.9v.4h-2.9z"/>
<path d="M150.3 183.6h3v.3h-3zM150.3 184.3h3v.4h-3zM155.9 183.6h3v.3h-3zM155.9 184.3h3v.4h-3zM161.5 183.6h2.9v.3h-2.9zM161.5 184.3h2.9v.4h-2.9zM168.9 184.3h3v.4h-3zM168.9 183.6h3v.3h-3zM176.3 184.3h3v.4h-3zM176.3 183.6h3v.3h-3z"/>
</g>
<path d="M81.4 118.9h5.5v8.1h-5.5zM81.4 128.1h5.5v8.2h-5.5zM81.4 146.7h5.5v8.1h-5.5zM81.4 155.9h5.5v8.2h-5.5z" fill="none" stroke="#000" stroke-width=".32"/>
<path d="M25.8 31.2h242.8M25.8 25.6h72.3M25.8 20.1h142.7M25.8 36.7h5.5l1.9 1.9v122.4M36.9 31.2l3.7 3.7v70.4M259.4 31.2l3.7 3.7v81.6M85.1 68.3v44.5l3.7 3.7h11.1l3.7 3.7v42.6l1.9 1.9h163.1M220.4 79.4v74.1l3.7 3.7h44.5M148.1 84.9v72.3l3.7 3.8h116.8M99.9 122v44.5l1.9 1.9h166.8" fill="none" stroke="#000" stroke-width=".57"/>
<g fill="#000" stroke="#000" stroke-width=".17">
<circle cx="36.9" cy="44.2" r=".38"/>
<circle cx="155.5" cy="55.3" r=".38"/>
<circle cx="159.2" cy="51.6" r=".38"/>
<circle cx="162.9" cy="47.9" r=".38"/>
<circle cx="36.9" cy="83.1" r=".38"/>
<circle cx="88.8" cy="94.2" r=".38"/>
<circle cx="116.6" cy="97.9" r=".38"/>
<circle cx="92.5" cy="103.5" r=".38"/>
<circle cx="112.9" cy="110.9" r=".38"/>
<circle cx="116.6" cy="105.3" r=".38"/>
<circle cx="116.6" cy="107.2" r=".38"/>
<circle cx="116.6" cy="112.8" r=".38"/>
<circle cx="116.6" cy="114.6" r=".38"/>
<circle cx="116.6" cy="116.5" r=".38"/>
<circle cx="213" cy="105.3" r=".38"/>
<circle cx="227.8" cy="101.6" r=".38"/>
<circle cx="38.7" cy="138.7" r=".38"/>
<circle cx="124" cy="179.5" r=".38"/>
<circle cx="129.6" cy="179.5" r=".38"/>
<circle cx="135.1" cy="179.5" r=".38"/>
<circle cx="140.7" cy="179.5" r=".38"/>
<circle cx="146.3" cy="179.5" r=".38"/>
<circle cx="151.8" cy="179.5" r=".38"/>
<circle cx="157.4" cy="179.5" r=".38"/>
<circle cx="162.9" cy="179.5" r=".38"/>
<circle cx="118.4" cy="188.8" r=".38"/>
<circle cx="124" cy="188.8" r=".38"/>
<circle cx="129.6" cy="188.8" r=".38"/>
<circle cx="135.1" cy="188.8" r=".38"/>
<circle cx="140.7" cy="188.8" r=".38"/>
<circle cx="146.3" cy="188.8" r=".38"/>
<circle cx="151.8" cy="188.8" r=".38"/>
<circle cx="157.4" cy="188.8" r=".38"/>
</g>
<use href="#words"/>
</svg>
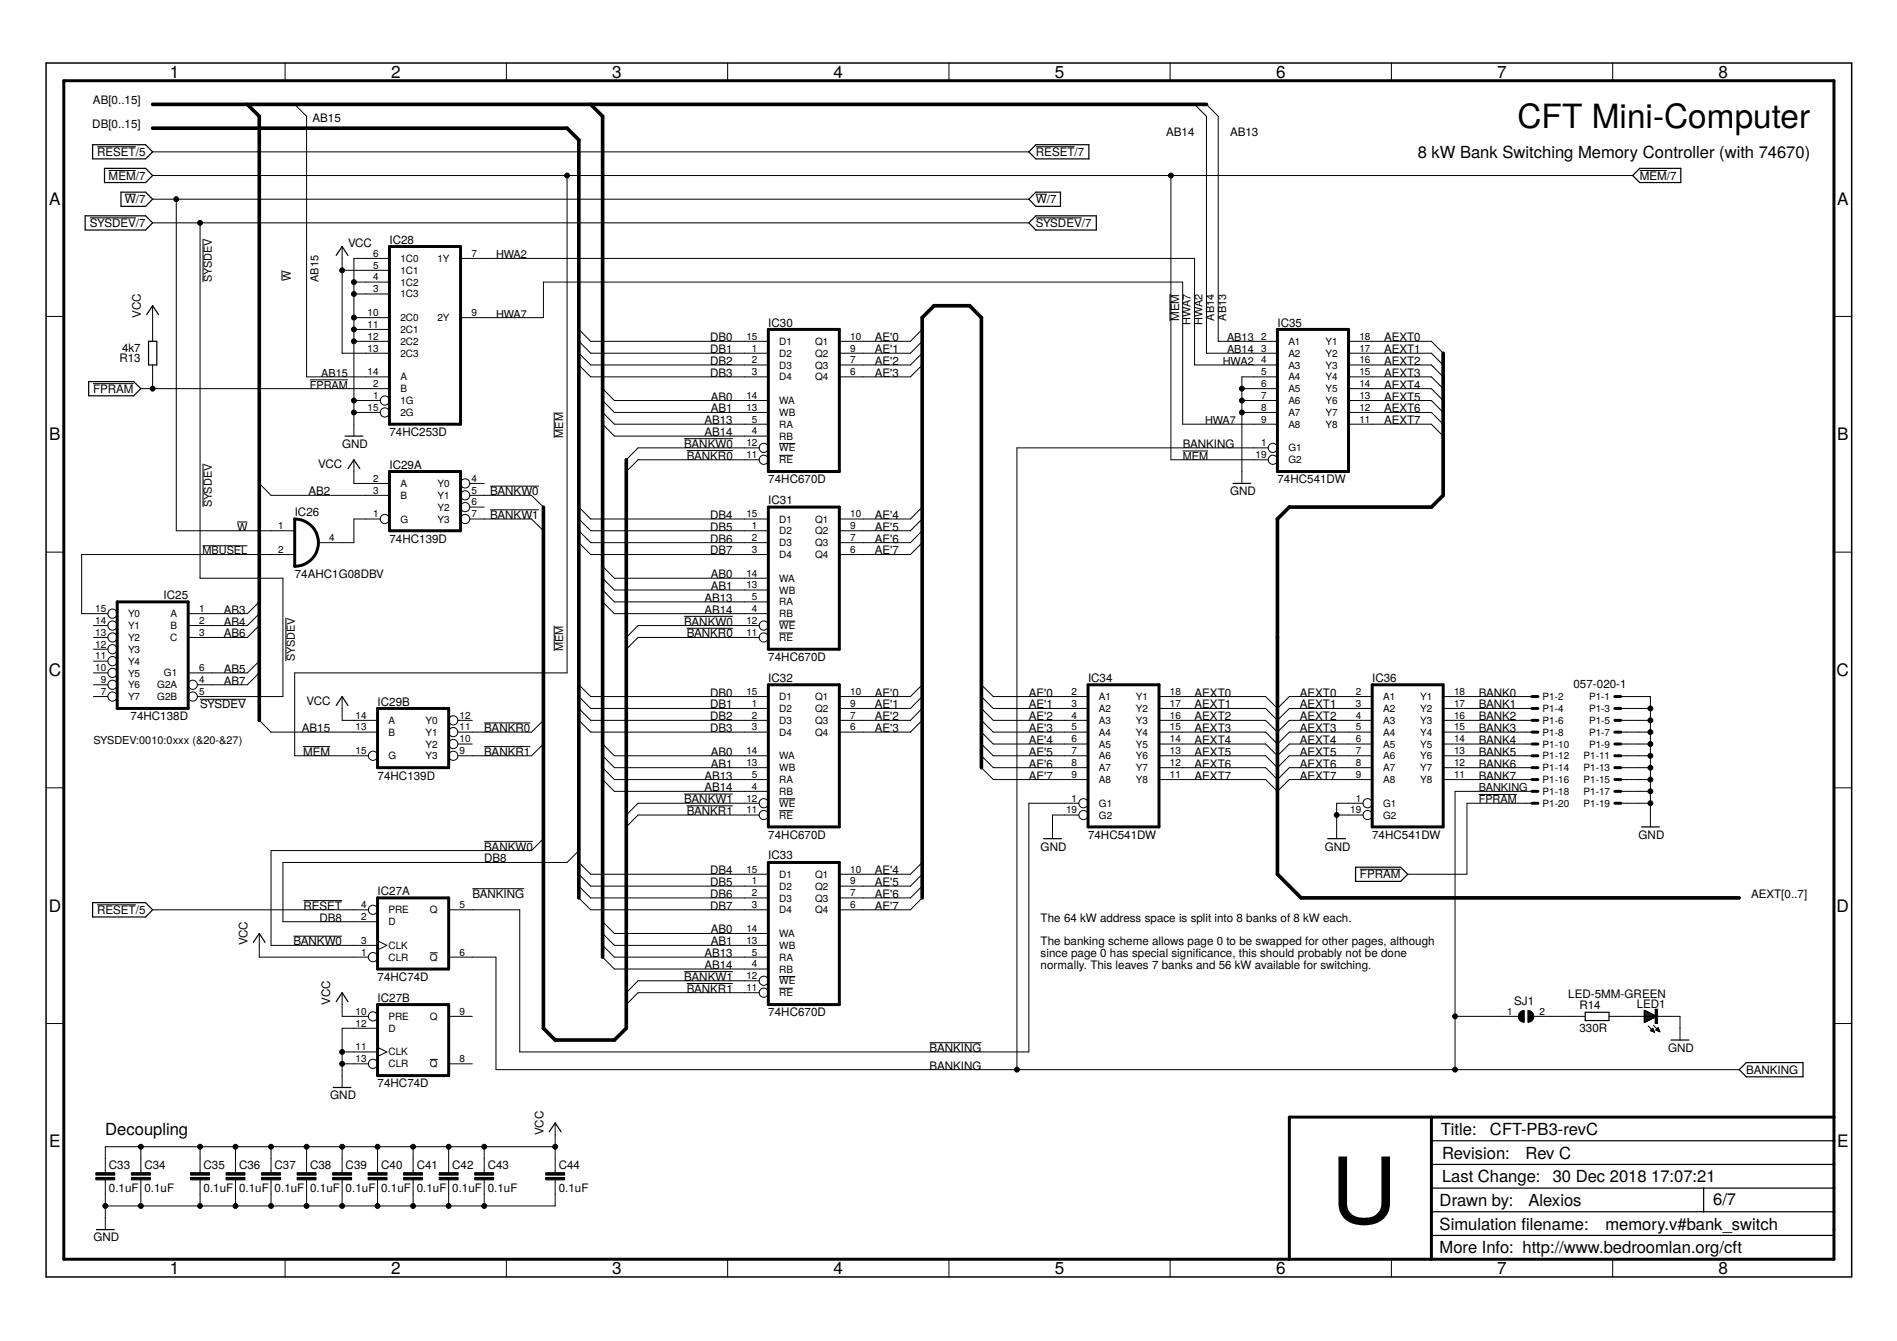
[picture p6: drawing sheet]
<svg xmlns="http://www.w3.org/2000/svg" width="297mm" height="210mm" viewBox="0 0 297 210" stroke-linecap="round" stroke-linejoin="round" font-family="sans-serif">
<defs><g id="words">
<text font-size="14.4" x="208.4" y="191.5">U</text>
<text font-size="5.2" x="237.6" y="20.1">CFT Mini-Computer</text>
<g font-size="2.7">
<text x="26.6" y="12.2">1</text>
<text x="61.2" y="12.2">2</text>
<text x="95.9" y="12.2">3</text>
<text x="130.5" y="12.2">4</text>
<text x="165.2" y="12.2">5</text>
<text x="199.8" y="12.2">6</text>
<text x="234.5" y="12.2">7</text>
<text x="269.1" y="12.2">8</text>
<text x="7.7" y="32">A</text>
<text x="287.7" y="32">A</text>
<text x="7.7" y="68.9">B</text>
<text x="287.7" y="68.9">B</text>
<text x="7.6" y="105.8">C</text>
<text x="287.6" y="105.8">C</text>
<text x="7.6" y="142.7">D</text>
<text x="287.6" y="142.7">D</text>
<text x="7.7" y="179.6">E</text>
<text x="287.7" y="179.6">E</text>
<text x="26.6" y="199.4">1</text>
<text x="61.2" y="199.4">2</text>
<text x="95.9" y="199.4">3</text>
<text x="130.5" y="199.4">4</text>
<text x="165.2" y="199.4">5</text>
<text x="199.8" y="199.4">6</text>
<text x="234.5" y="199.4">7</text>
<text x="269.1" y="199.4">8</text>
</g>
<g font-size="2.6">
<text x="222" y="24.7">8 kW Bank Switching Memory Controller (with 74670)</text>
<text x="16.5" y="177.6">Decoupling</text>
<text x="225.6" y="177.6">Title:</text>
<text x="233.3" y="177.7">CFT-PB3-revC</text>
<text x="225.8" y="181.3">Revision:</text>
<text x="225.8" y="185">Last Change:</text>
<text x="238.9" y="181.4">Rev C</text>
<text x="243.1" y="185">30 Dec 2018</text>
<text x="258.6" y="185">17:07:21</text>
<text x="225.4" y="188.8">Drawn by:</text>
<text x="239.3" y="188.8">Alexios</text>
<text x="268.3" y="188.7">6/7</text>
<text x="225.4" y="192.5">Simulation flename:</text>
<text x="225.4" y="196.2">More Info: http://www.bedroomlan.org/cft</text>
<text x="238.2" y="192.5">i</text>
<text x="251.4" y="192.5">memory.v#bank_switch</text>
</g>
<g font-size="1.8">
<text x="14.6" y="16.3">AB[0..15]</text>
<text x="14.5" y="20.1">DB[0..15]</text>
<text x="48.9" y="19.1">AB15</text>
<text x="182.6" y="21.3">AB14</text>
<text x="192.6" y="21.3">AB13</text>
<text x="15.2" y="24.4">RESET/5</text>
<text x="17" y="28.1">MEM/7</text>
<text x="162.2" y="24.4">RESET/7</text>
<text x="256.8" y="28.1">MEM/7</text>
<text x="14.1" y="35.5">SYSDEV/7</text>
<text x="19.6" y="31.8">W/7</text>
<text x="162.2" y="31.8">W/7</text>
<text x="162.2" y="35.5">SYSDEV/7</text>
<text x="54.5" y="38.6">VCC</text>
<text x="61" y="38.1">IC28</text>
<text x="22" y="49.7" transform="rotate(-90 22 49.7)">VCC</text>
<text x="111.2" y="53.4">DB0</text>
<text x="120.3" y="51.1">IC30</text>
<text x="137" y="53.4">AE'0</text>
<text x="184.6" y="50.3" transform="rotate(-90 184.6 50.3)">MEM</text>
<text x="200" y="51.1">IC35</text>
<text x="216.7" y="53.4">AEXT0</text>
<text x="18.7" y="56.7">R13</text>
<text x="19.1" y="55.1">4k7</text>
<text x="111.2" y="55.3">DB1</text>
<text x="111.2" y="57.1">DB2</text>
<text x="111.2" y="59">DB3</text>
<text x="137" y="55.3">AE'1</text>
<text x="137" y="57.1">AE'2</text>
<text x="137" y="59">AE'3</text>
<text x="216.7" y="55.3">AEXT1</text>
<text x="216.7" y="57.1">AEXT2</text>
<text x="216.7" y="59">AEXT3</text>
<text x="14.6" y="61.5">FPRAM</text>
<text x="111.3" y="62.7">AB0</text>
<text x="111.3" y="64.5">AB1</text>
<text x="216.7" y="60.8">AEXT4</text>
<text x="216.7" y="62.7">AEXT5</text>
<text x="216.7" y="64.5">AEXT6</text>
<text x="53.6" y="70.1">GND</text>
<text x="61" y="68.3">74HC253D</text>
<text x="107.1" y="70.1">BANKW0</text>
<text x="107.5" y="72">BANKR0</text>
<text x="110.3" y="66.4">AB13</text>
<text x="110.3" y="68.3">AB14</text>
<text x="185.2" y="70.1">BANKING</text>
<text x="216.7" y="66.4">AEXT7</text>
<text x="48.3" y="77.5">AB2</text>
<text x="49.8" y="73.3">VCC</text>
<text x="61" y="73.4">IC29A</text>
<text x="76.7" y="77.5">BANKW0</text>
<text x="120.3" y="75.7">74HC670D</text>
<text x="192.6" y="77.5">GND</text>
<text x="200" y="75.7">74HC541DW</text>
<text x="46.2" y="80.8">IC26</text>
<text x="76.7" y="81.2">BANKW1</text>
<text x="111.2" y="81.2">DB4</text>
<text x="111.2" y="83.1">DB5</text>
<text x="120.3" y="78.9">IC31</text>
<text x="137" y="81.2">AE'4</text>
<text x="137" y="83.1">AE'5</text>
<text x="61" y="84.9">74HC139D</text>
<text x="111.2" y="84.9">DB6</text>
<text x="111.2" y="86.8">DB7</text>
<text x="137" y="84.9">AE'6</text>
<text x="137" y="86.8">AE'7</text>
<text x="25.6" y="93.7">IC25</text>
<text x="46.2" y="90.5">74AHC1G08DBV</text>
<text x="110.3" y="94.2">AB13</text>
<text x="111.3" y="90.5">AB0</text>
<text x="111.3" y="92.4">AB1</text>
<text x="35" y="96.1">AB3</text>
<text x="35" y="97.9">AB4</text>
<text x="35" y="99.8">AB6</text>
<text x="107.1" y="97.9">BANKW0</text>
<text x="107.5" y="99.8">BANKR0</text>
<text x="110.3" y="96.1">AB14</text>
<text x="35" y="105.3">AB5</text>
<text x="35" y="107.2">AB7</text>
<text x="120.3" y="103.5">74HC670D</text>
<text x="120.3" y="106.7">IC32</text>
<text x="170.4" y="106.7">IC34</text>
<text x="214.9" y="106.7">IC36</text>
<text x="246.4" y="107.6">057-020-1</text>
<text x="20.4" y="112.7">74HC138D</text>
<text x="31.3" y="110.9">SYSDEV</text>
<text x="48" y="110.3">VCC</text>
<text x="59.1" y="110.4">IC29B</text>
<text x="111.2" y="109">DB0</text>
<text x="111.2" y="110.9">DB1</text>
<text x="111.2" y="112.7">DB2</text>
<text x="137" y="109">AE'0</text>
<text x="137" y="110.9">AE'1</text>
<text x="137" y="112.7">AE'2</text>
<text x="161.1" y="109">AE'0</text>
<text x="161.1" y="110.9">AE'1</text>
<text x="161.1" y="112.7">AE'2</text>
<text x="187.1" y="109">AEXT0</text>
<text x="187.1" y="110.9">AEXT1</text>
<text x="187.1" y="112.7">AEXT2</text>
<text x="203.5" y="109">AEXT0</text>
<text x="203.5" y="110.9">AEXT1</text>
<text x="203.5" y="112.7">AEXT2</text>
<text x="231.5" y="109">BANK0</text>
<text x="231.5" y="110.9">BANK1</text>
<text x="231.5" y="112.7">BANK2</text>
<text x="47.3" y="114.6">AB15</text>
<text x="47.5" y="118.3">MEM</text>
<text x="75.8" y="114.6">BANKR0</text>
<text x="75.8" y="118.3">BANKR1</text>
<text x="111.2" y="114.6">DB3</text>
<text x="111.3" y="118.3">AB0</text>
<text x="137" y="114.6">AE'3</text>
<text x="161.1" y="114.6">AE'3</text>
<text x="161.1" y="116.5">AE'4</text>
<text x="161.1" y="118.3">AE'5</text>
<text x="187.1" y="114.6">AEXT3</text>
<text x="187.1" y="116.5">AEXT4</text>
<text x="187.1" y="118.3">AEXT5</text>
<text x="203.5" y="114.6">AEXT3</text>
<text x="203.5" y="116.5">AEXT4</text>
<text x="203.5" y="118.3">AEXT5</text>
<text x="231.5" y="114.6">BANK3</text>
<text x="231.5" y="116.5">BANK4</text>
<text x="231.5" y="118.3">BANK5</text>
<text x="59.1" y="122">74HC139D</text>
<text x="107.1" y="125.7">BANKW1</text>
<text x="110.3" y="122">AB13</text>
<text x="110.3" y="123.9">AB14</text>
<text x="111.3" y="120.2">AB1</text>
<text x="161.1" y="120.2">AE'6</text>
<text x="161.1" y="122">AE'7</text>
<text x="187.1" y="120.2">AEXT6</text>
<text x="187.1" y="122">AEXT7</text>
<text x="203.5" y="120.2">AEXT6</text>
<text x="203.5" y="122">AEXT7</text>
<text x="231.5" y="120.2">BANK6</text>
<text x="231.5" y="122">BANK7</text>
<text x="107.5" y="127.6">BANKR1</text>
<text x="120.3" y="131.3">74HC670D</text>
<text x="170.4" y="131.3">74HC541DW</text>
<text x="214.9" y="131.3">74HC541DW</text>
<text x="256.6" y="131.3">GND</text>
<text x="75.8" y="133.1">BANKW0</text>
<text x="75.8" y="135">DB8</text>
<text x="111.2" y="136.8">DB4</text>
<text x="120.3" y="134.5">IC33</text>
<text x="137" y="136.8">AE'4</text>
<text x="162.9" y="133.1">GND</text>
<text x="207.4" y="133.1">GND</text>
<text x="212.9" y="137.5">FPRAM</text>
<text x="15.2" y="143.1">RESET/5</text>
<text x="47.5" y="142.4">RESET</text>
<text x="59.1" y="140.1">IC27A</text>
<text x="74" y="140.6">BANKING</text>
<text x="111.2" y="138.7">DB5</text>
<text x="111.2" y="140.6">DB6</text>
<text x="111.2" y="142.4">DB7</text>
<text x="137" y="138.7">AE'5</text>
<text x="137" y="140.6">AE'6</text>
<text x="137" y="142.4">AE'7</text>
<text x="274.2" y="140.6">AEXT[0..7]</text>
<text x="38.7" y="148" transform="rotate(-90 38.7 148)">VCC</text>
<text x="45.9" y="148">BANKW0</text>
<text x="50" y="144.3">DB8</text>
<text x="110.3" y="149.8">AB13</text>
<text x="111.3" y="146.1">AB0</text>
<text x="111.3" y="148">AB1</text>
<text x="162.9" y="144.3">The 64 kW address space is split into 8 banks of 8 kW each.</text>
<text x="162.9" y="148">The banking scheme allows page 0 to be swapped for other pages, although</text>
<text x="162.9" y="149.8">since page 0 has special signifcance, this should probably not be done</text>
<text x="187.2" y="149.8">i</text>
<text x="59.1" y="153.5">74HC74D</text>
<text x="107.1" y="153.5">BANKW1</text>
<text x="107.5" y="155.4">BANKR1</text>
<text x="110.3" y="151.7">AB14</text>
<text x="162.9" y="151.7">normally. This leaves 7 banks and 56 kW available for switching.</text>
<text x="51.7" y="157.2" transform="rotate(-90 51.7 157.2)">VCC</text>
<text x="59.1" y="156.8">IC27B</text>
<text x="120.3" y="159.1">74HC670D</text>
<text x="237.1" y="157.2">SJ1</text>
<text x="245.6" y="156.2">LED-5MM-GREEN</text>
<text x="247.3" y="161.5">330R</text>
<text x="247.3" y="158">R14</text>
<text x="256.3" y="157.8">LED1</text>
<text x="145.6" y="164.7">BANKING</text>
<text x="145.6" y="167.4">BANKING</text>
<text x="261.2" y="164.7">GND</text>
<text x="51.7" y="172.1">GND</text>
<text x="59.1" y="170.2">74HC74D</text>
<text x="273.4" y="168.1">BANKING</text>
<text x="85.1" y="177.6" transform="rotate(-90 85.1 177.6)">VCC</text>
<text x="17" y="182.9">C33</text>
<text x="22.6" y="182.9">C34</text>
<text x="31.9" y="182.9">C35</text>
<text x="37.4" y="182.9">C36</text>
<text x="43" y="182.9">C37</text>
<text x="48.6" y="182.9">C38</text>
<text x="54.1" y="182.9">C39</text>
<text x="59.7" y="182.9">C40</text>
<text x="65.2" y="182.9">C41</text>
<text x="70.8" y="182.9">C42</text>
<text x="76.4" y="182.9">C43</text>
<text x="87.5" y="182.9">C44</text>
<text x="17" y="186.6">0.1uF 0.1uF</text>
<text x="31.9" y="186.6">0.1uF 0.1uF 0.1uF 0.1uF 0.1uF 0.1uF 0.1uF 0.1uF 0.1uF</text>
<text x="87.5" y="186.6">0.1uF</text>
<text x="14.6" y="194.3">GND</text>
</g>
<g font-size="1.7">
<text x="77.7" y="40.4">HWA2</text>
<text x="33.2" y="44.2" transform="rotate(-90 33.2 44.2)">SYSDEV</text>
<text x="45.5" y="43.9" transform="rotate(-90 45.5 43.9)">W</text>
<text x="49.9" y="44.2" transform="rotate(-90 49.9 44.2)">AB15</text>
<text x="77.7" y="49.7">HWA7</text>
<text x="186.4" y="50.9" transform="rotate(-90 186.4 50.9)">HWA7</text>
<text x="188.3" y="50.9" transform="rotate(-90 188.3 50.9)">HWA2</text>
<text x="190.1" y="50.2" transform="rotate(-90 190.1 50.2)">AB14</text>
<text x="192" y="50.2" transform="rotate(-90 192 50.2)">AB13</text>
<text x="192.1" y="53.4">AB13</text>
<text x="50.3" y="59">AB15</text>
<text x="191.5" y="57.1">HWA2</text>
<text x="192.1" y="55.3">AB14</text>
<text x="48.5" y="60.8">FPRAM</text>
<text x="88.2" y="68.5" transform="rotate(-90 88.2 68.5)">MEM</text>
<text x="185.2" y="72">MEM</text>
<text x="188.7" y="66.4">HWA7</text>
<text x="33.2" y="79.4" transform="rotate(-90 33.2 79.4)">SYSDEV</text>
<text x="37.1" y="83.1">W</text>
<text x="31.7" y="86.8">MBUSEL</text>
<text x="88.2" y="101.9" transform="rotate(-90 88.2 101.9)">MEM</text>
<text x="46.2" y="103.5" transform="rotate(-90 46.2 103.5)">SYSDEV</text>
<text x="14.6" y="116.5">SYSDEV:0010:0xxx (&amp;20-&amp;27)</text>
<text x="231.5" y="125.7">FPRAM</text>
<text x="231.5" y="123.9">BANKING</text>
</g>
<g font-size="1.6">
<text x="58.4" y="40.2">6</text>
<text x="62.7" y="41">1C0</text>
<text x="68.5" y="41">1Y</text>
<text x="73.8" y="40.2">7</text>
<text x="58.4" y="45.8">3</text>
<text x="58.4" y="43.9">4</text>
<text x="58.4" y="42">5</text>
<text x="62.7" y="46.6">1C3</text>
<text x="62.7" y="44.7">1C2</text>
<text x="62.7" y="42.9">1C1</text>
<text x="57.5" y="49.5">10</text>
<text x="57.5" y="51.3">11</text>
<text x="57.5" y="53.2">12</text>
<text x="62.7" y="50.3">2C0</text>
<text x="62.7" y="52.1">2C1</text>
<text x="62.7" y="54">2C2</text>
<text x="68.5" y="50.3">2Y</text>
<text x="73.8" y="49.5">9</text>
<text x="116.9" y="53.2">15</text>
<text x="122" y="54">D1</text>
<text x="127.6" y="54">Q1</text>
<text x="133.1" y="53.2">10</text>
<text x="197.5" y="53.2">2</text>
<text x="201.7" y="54">A1</text>
<text x="207.5" y="54">Y1</text>
<text x="212.9" y="53.2">18</text>
<text x="57.5" y="55">13</text>
<text x="57.5" y="58.7">14</text>
<text x="62.7" y="55.8">2C3</text>
<text x="62.7" y="59.5">A</text>
<text x="117.7" y="55">1</text>
<text x="117.7" y="56.9">2</text>
<text x="117.7" y="58.7">3</text>
<text x="122" y="55.8">D2</text>
<text x="122" y="57.7">D3</text>
<text x="122" y="59.5">D4</text>
<text x="127.6" y="59.6">Q4</text>
<text x="127.6" y="57.7">Q3</text>
<text x="127.6" y="55.8">Q2</text>
<text x="133.1" y="58.7">6</text>
<text x="133.1" y="56.9">7</text>
<text x="133.1" y="55">9</text>
<text x="197.5" y="55">3</text>
<text x="197.5" y="56.9">4</text>
<text x="197.5" y="58.7">5</text>
<text x="201.7" y="55.8">A2</text>
<text x="201.7" y="57.7">A3</text>
<text x="201.7" y="59.5">A4</text>
<text x="207.5" y="59.6">Y4</text>
<text x="207.5" y="57.7">Y3</text>
<text x="207.5" y="55.8">Y2</text>
<text x="212.9" y="58.7">15</text>
<text x="212.9" y="56.9">16</text>
<text x="212.9" y="55">17</text>
<text x="57.5" y="64.3">15</text>
<text x="58.4" y="62.4">1</text>
<text x="58.4" y="60.6">2</text>
<text x="62.7" y="63.3">1G</text>
<text x="62.7" y="61.4">B</text>
<text x="62.7" y="65.1">2G</text>
<text x="116.9" y="64.3">13</text>
<text x="116.9" y="62.4">14</text>
<text x="122" y="65.1">WB</text>
<text x="122" y="63.3">WA</text>
<text x="197.5" y="60.6">6</text>
<text x="197.5" y="62.4">7</text>
<text x="197.5" y="64.3">8</text>
<text x="201.7" y="61.4">A5</text>
<text x="201.7" y="63.3">A6</text>
<text x="201.7" y="65.1">A7</text>
<text x="207.5" y="65.1">Y7</text>
<text x="207.5" y="63.3">Y6</text>
<text x="207.5" y="61.4">Y5</text>
<text x="212.9" y="64.3">12</text>
<text x="212.9" y="62.4">13</text>
<text x="212.9" y="60.6">14</text>
<text x="116.9" y="71.7">11</text>
<text x="116.9" y="69.9">12</text>
<text x="117.7" y="68">4</text>
<text x="117.7" y="66.1">5</text>
<text x="122" y="68.8">RB</text>
<text x="122" y="67">RA</text>
<text x="122" y="70.7">WE</text>
<text x="196.6" y="71.7">19</text>
<text x="197.5" y="69.9">1</text>
<text x="197.5" y="66.1">9</text>
<text x="201.7" y="70.7">G1</text>
<text x="201.7" y="67">A8</text>
<text x="207.5" y="67">Y8</text>
<text x="212.9" y="66.1">11</text>
<text x="58.4" y="75.4">2</text>
<text x="58.4" y="77.3">3</text>
<text x="62.7" y="76.2">A</text>
<text x="68.5" y="76.2">Y0</text>
<text x="73.8" y="75.4">4</text>
<text x="73.8" y="77.3">5</text>
<text x="122" y="72.5">RE</text>
<text x="201.7" y="72.5">G2</text>
<text x="43.6" y="82.8">1</text>
<text x="58.4" y="81">1</text>
<text x="62.7" y="81.8">G</text>
<text x="62.7" y="78.1">B</text>
<text x="68.5" y="78.1">Y1</text>
<text x="68.5" y="79.9">Y2</text>
<text x="68.5" y="81.8">Y3</text>
<text x="73.8" y="79.1">6</text>
<text x="73.8" y="81">7</text>
<text x="116.9" y="81">15</text>
<text x="117.7" y="82.8">1</text>
<text x="122" y="83.6">D2</text>
<text x="122" y="81.8">D1</text>
<text x="127.6" y="83.7">Q2</text>
<text x="127.6" y="81.8">Q1</text>
<text x="133.1" y="82.8">9</text>
<text x="133.1" y="81">10</text>
<text x="43.6" y="86.5">2</text>
<text x="51.6" y="84.7">4</text>
<text x="117.7" y="84.7">2</text>
<text x="117.7" y="86.5">3</text>
<text x="122" y="85.5">D3</text>
<text x="122" y="87.4">D4</text>
<text x="127.6" y="87.4">Q4</text>
<text x="127.6" y="85.5">Q3</text>
<text x="133.1" y="86.5">6</text>
<text x="133.1" y="84.7">7</text>
<text x="14.9" y="95.8">15</text>
<text x="31.2" y="95.8">1</text>
<text x="116.9" y="92.1">13</text>
<text x="116.9" y="90.2">14</text>
<text x="117.7" y="95.8">4</text>
<text x="117.7" y="93.9">5</text>
<text x="122" y="94.8">RA</text>
<text x="122" y="92.9">WB</text>
<text x="122" y="91.1">WA</text>
<text x="14.9" y="101.4">12</text>
<text x="14.9" y="99.5">13</text>
<text x="14.9" y="97.7">14</text>
<text x="20" y="100.3">Y2</text>
<text x="20" y="98.5">Y1</text>
<text x="20" y="96.6">Y0</text>
<text x="26.6" y="100.3">C</text>
<text x="26.7" y="96.6">A</text>
<text x="26.7" y="98.5">B</text>
<text x="31.2" y="97.7">2</text>
<text x="31.2" y="99.5">3</text>
<text x="116.9" y="99.5">11</text>
<text x="116.9" y="97.7">12</text>
<text x="122" y="96.6">RB</text>
<text x="122" y="100.3">RE</text>
<text x="122" y="98.5">WE</text>
<text x="14.9" y="105.1">10</text>
<text x="14.9" y="103.2">11</text>
<text x="15.8" y="106.9">9</text>
<text x="20" y="107.8">Y6</text>
<text x="20" y="105.9">Y5</text>
<text x="20" y="104">Y4</text>
<text x="20" y="102.2">Y3</text>
<text x="24.6" y="107.7">G2A</text>
<text x="25.7" y="105.9">G1</text>
<text x="31.2" y="106.9">4</text>
<text x="31.2" y="105.1">6</text>
<text x="15.8" y="108.8">7</text>
<text x="20" y="109.6">Y7</text>
<text x="24.6" y="109.6">G2B</text>
<text x="31.2" y="108.8">5</text>
<text x="55.7" y="112.5">14</text>
<text x="60.8" y="113.3">A</text>
<text x="66.6" y="113.3">Y0</text>
<text x="72" y="112.5">12</text>
<text x="116.9" y="108.8">15</text>
<text x="117.7" y="110.6">1</text>
<text x="117.7" y="112.5">2</text>
<text x="122" y="111.4">D2</text>
<text x="122" y="113.3">D3</text>
<text x="122" y="109.6">D1</text>
<text x="127.6" y="113.3">Q3</text>
<text x="127.6" y="111.5">Q2</text>
<text x="127.6" y="109.6">Q1</text>
<text x="133.1" y="112.5">7</text>
<text x="133.1" y="110.6">9</text>
<text x="133.1" y="108.8">10</text>
<text x="167.8" y="108.8">2</text>
<text x="167.8" y="110.6">3</text>
<text x="167.8" y="112.5">4</text>
<text x="172.1" y="109.6">A1</text>
<text x="172.1" y="111.4">A2</text>
<text x="172.1" y="113.3">A3</text>
<text x="177.9" y="113.3">Y3</text>
<text x="177.9" y="111.5">Y2</text>
<text x="177.9" y="109.6">Y1</text>
<text x="183.2" y="112.5">16</text>
<text x="183.2" y="110.6">17</text>
<text x="183.2" y="108.8">18</text>
<text x="212.3" y="108.8">2</text>
<text x="212.3" y="110.6">3</text>
<text x="212.3" y="112.5">4</text>
<text x="216.6" y="109.6">A1</text>
<text x="216.6" y="111.4">A2</text>
<text x="216.6" y="113.3">A3</text>
<text x="222.4" y="113.3">Y3</text>
<text x="222.4" y="111.5">Y2</text>
<text x="222.4" y="109.6">Y1</text>
<text x="227.7" y="112.5">16</text>
<text x="227.7" y="110.6">17</text>
<text x="227.7" y="108.8">18</text>
<text x="241.6" y="109.6">P1-2</text>
<text x="241.6" y="111.4">P1-4</text>
<text x="241.6" y="113.3">P1-6</text>
<text x="248.8" y="109.6">P1-1</text>
<text x="248.8" y="111.4">P1-3</text>
<text x="248.8" y="113.3">P1-5</text>
<text x="55.7" y="118">15</text>
<text x="55.7" y="114.3">13</text>
<text x="60.8" y="118.9">G</text>
<text x="60.8" y="115.2">B</text>
<text x="66.6" y="115.2">Y1</text>
<text x="66.6" y="117">Y2</text>
<text x="66.6" y="118.9">Y3</text>
<text x="72" y="114.3">11</text>
<text x="72" y="116.2">10</text>
<text x="72" y="118">9</text>
<text x="116.9" y="119.9">13</text>
<text x="116.9" y="118">14</text>
<text x="117.7" y="114.3">3</text>
<text x="122" y="115.2">D4</text>
<text x="122" y="118.9">WA</text>
<text x="127.6" y="115.2">Q4</text>
<text x="133.1" y="114.3">6</text>
<text x="167.8" y="114.3">5</text>
<text x="167.8" y="116.2">6</text>
<text x="167.8" y="118">7</text>
<text x="167.8" y="119.9">8</text>
<text x="172.1" y="115.2">A4</text>
<text x="172.1" y="117">A5</text>
<text x="172.1" y="118.9">A6</text>
<text x="177.9" y="118.9">Y6</text>
<text x="177.9" y="117">Y5</text>
<text x="177.9" y="115.2">Y4</text>
<text x="183.2" y="119.9">12</text>
<text x="183.2" y="118">13</text>
<text x="183.2" y="116.2">14</text>
<text x="183.2" y="114.3">15</text>
<text x="212.3" y="114.3">5</text>
<text x="212.3" y="116.2">6</text>
<text x="212.3" y="118">7</text>
<text x="212.3" y="119.9">8</text>
<text x="216.6" y="115.2">A4</text>
<text x="216.6" y="117">A5</text>
<text x="216.6" y="118.9">A6</text>
<text x="222.4" y="118.9">Y6</text>
<text x="222.4" y="117">Y5</text>
<text x="222.4" y="115.2">Y4</text>
<text x="227.7" y="119.9">12</text>
<text x="227.7" y="118">13</text>
<text x="227.7" y="116.2">14</text>
<text x="227.7" y="114.3">15</text>
<text x="241.6" y="115.2">P1-8</text>
<text x="241.6" y="117">P1-10</text>
<text x="241.6" y="118.9">P1-12</text>
<text x="248" y="118.9">P1-11</text>
<text x="248.8" y="115.2">P1-7</text>
<text x="248.8" y="117">P1-9</text>
<text x="116.9" y="125.5">12</text>
<text x="117.7" y="123.6">4</text>
<text x="117.7" y="121.8">5</text>
<text x="122" y="124.4">RB</text>
<text x="122" y="122.6">RA</text>
<text x="122" y="120.7">WB</text>
<text x="167.8" y="125.5">1</text>
<text x="167.8" y="121.8">9</text>
<text x="172.1" y="120.7">A7</text>
<text x="172.1" y="122.6">A8</text>
<text x="177.9" y="122.6">Y8</text>
<text x="177.9" y="120.7">Y7</text>
<text x="183.2" y="121.8">11</text>
<text x="212.3" y="125.5">1</text>
<text x="212.3" y="121.8">9</text>
<text x="216.6" y="120.7">A7</text>
<text x="216.6" y="122.6">A8</text>
<text x="222.4" y="122.6">Y8</text>
<text x="222.4" y="120.7">Y7</text>
<text x="227.7" y="121.8">11</text>
<text x="241.6" y="120.7">P1-14</text>
<text x="241.6" y="122.6">P1-16</text>
<text x="241.6" y="124.4">P1-18</text>
<text x="248" y="120.7">P1-13</text>
<text x="248" y="122.6">P1-15</text>
<text x="248" y="124.4">P1-17</text>
<text x="116.9" y="127.3">11</text>
<text x="122" y="128.1">RE</text>
<text x="122" y="126.3">WE</text>
<text x="166.9" y="127.3">19</text>
<text x="172.1" y="126.3">G1</text>
<text x="172.1" y="128.1">G2</text>
<text x="211.4" y="127.3">19</text>
<text x="216.6" y="126.3">G1</text>
<text x="216.6" y="128.1">G2</text>
<text x="241.6" y="126.3">P1-20</text>
<text x="248" y="126.3">P1-19</text>
<text x="116.9" y="136.6">15</text>
<text x="122" y="137.4">D1</text>
<text x="127.6" y="137.4">Q1</text>
<text x="133.1" y="136.6">10</text>
<text x="56.6" y="142.1">4</text>
<text x="60.8" y="143">PRE</text>
<text x="67.3" y="143">Q</text>
<text x="72" y="142.1">5</text>
<text x="117.7" y="138.4">1</text>
<text x="117.7" y="140.3">2</text>
<text x="117.7" y="142.1">3</text>
<text x="122" y="139.3">D2</text>
<text x="122" y="141.1">D3</text>
<text x="122" y="143">D4</text>
<text x="127.6" y="143">Q4</text>
<text x="127.6" y="141.1">Q3</text>
<text x="127.6" y="139.3">Q2</text>
<text x="133.1" y="142.1">6</text>
<text x="133.1" y="140.3">7</text>
<text x="133.1" y="138.4">9</text>
<text x="56.6" y="149.6">1</text>
<text x="56.6" y="144">2</text>
<text x="56.6" y="147.7">3</text>
<text x="60.8" y="144.8">D</text>
<text x="60.8" y="148.5">CLK</text>
<text x="72" y="149.6">6</text>
<text x="116.9" y="147.7">13</text>
<text x="116.9" y="145.9">14</text>
<text x="117.7" y="149.6">5</text>
<text x="122" y="148.5">WB</text>
<text x="122" y="146.7">WA</text>
<text x="60.8" y="150.4">CLR</text>
<text x="67.3" y="150.4">Q</text>
<text x="116.9" y="155.1">11</text>
<text x="116.9" y="153.3">12</text>
<text x="117.7" y="151.4">4</text>
<text x="122" y="152.2">RB</text>
<text x="122" y="150.4">RA</text>
<text x="122" y="155.9">RE</text>
<text x="122" y="154.1">WE</text>
<text x="55.7" y="160.7">12</text>
<text x="55.7" y="158.8">10</text>
<text x="60.8" y="161.5">D</text>
<text x="60.8" y="159.6">PRE</text>
<text x="67.3" y="159.7">Q</text>
<text x="72" y="158.8">9</text>
<text x="236" y="158.8">1</text>
<text x="241.1" y="158.8">2</text>
<text x="55.7" y="166.2">13</text>
<text x="55.7" y="164.4">11</text>
<text x="60.8" y="167.1">CLR</text>
<text x="60.8" y="165.2">CLK</text>
<text x="67.3" y="167.1">Q</text>
<text x="72" y="166.2">8</text>
</g>
</g></defs>
<g fill="none" stroke="#000" stroke-width=".16">
<path d="M10 12.6h277.2v184.5h-277.2zM44.6 9.9v2.7M46.1 16.3l1.9 1.9v40.8h13M79.3 9.9v2.7M113.9 9.9v2.7M148.6 9.9v2.7M183.2 9.9v2.7M187 16.3l1.9 1.9v37.1h11.1M188.9 16.3l1.9 1.9v35.2h9.2M217.9 9.9v2.7M252.5 9.9v2.7M14.1 34.1h7.2"/>
<path d="M15.2 23h6.1M17 26.7h4.3M19.6 30.4h1.7M23.9 31.2h137.2M23.9 23.8h137.2M23.9 34.9h137.2M23.9 27.5h231.8M27.6 31.2v51.9h18.5M31.3 34.9v55.6h13v18.5h-13.4M31.8 37.4v6.8M53.6 38.6v16.7h7.4M88.8 27.5v77.8h-42.7v13h11.6"/>
<path d="M162.2 30.4h1.7M162.2 23h6.1M162.2 34.1h7.2M183.3 27.5v44.5h15.3M256.8 26.7h4.2M7.2 49.5h2.8M23.9 47.9v5.5M23.9 57.1v3.7M44.2 42.3v1.6M48.5 59.5h6M53.6 42.3h7.4M55.4 53.4h5.6"/>
<path d="M55.4 46h5.6M55.4 44.2h5.6M55.4 49.7h5.6M55.4 51.6h5.6M61 40.4h-5.6v27.9M72.1 40.4h114.9v16.7h13M72.1 49.7h13v-5.5h100.1v22.2h14.8M90.6 51.6l1.9 1.8h27.8M90.6 53.4l1.9 1.9h27.8M90.6 55.3l1.9 1.8h27.8M90.6 57.1l1.9 1.9h27.8M144.4 51.6l-1.8 1.8h-11.2"/>
<path d="M144.4 53.4l-1.8 1.9h-11.2M144.4 55.3l-1.8 1.8h-11.2M144.4 57.1l-1.8 1.9h-11.2M183.2 46v4.3M200 59h-5.5v16.7M211.2 53.4h12.9l1.9 1.9M211.2 55.3h12.9l1.9 1.8M211.2 57.1h12.9l1.9 1.9M211.2 59h12.9l1.9 1.8M287.2 49.5h2.7M14.6 60h6.3M22.1 60.8h38.9"/>
<path d="M31.8 72.6v6.8M40.6 75.7l1.8 1.8h18.6M55.4 62.7h4.1M55.4 64.6h4.1M55.4 72v3.7h5.6M73.6 75.7h2.2M73.6 77.5h9.6l1.9 1.9M73.6 79.4h2.2M76.8 76.1h7.6M76.8 79.8h7.6M86.8 64.6v3.9M90.6 79.4l1.9 1.8h27.8"/>
<path d="M94.4 60.8l1.8 1.9h24.1M94.4 62.7l1.8 1.9h24.1M94.4 64.6l1.8 1.8h24.1M94.4 66.4l1.8 1.9h24.1M107.1 68.7h7.6M107.5 70.5h7.2M118.9 70.1h-19l-1.8 1.9M118.9 72h-19l-1.8 1.8M122 71.3h2.2M122 69.4h2.5M144.4 79.4l-1.8 1.8h-11.2M185.2 70.6h4"/>
<path d="M194.5 60.8h5.5M194.5 62.7h5.5M194.5 64.6h5.5M198.6 70.1h-39.4v97.3M211.2 60.8h12.9l1.9 1.9M211.2 62.7h12.9l1.9 1.9M211.2 64.6h12.9l1.9 1.8M211.2 66.4h12.9l1.9 1.9M7.2 86.4h2.8M14.6 99.8h2.3M14.6 97.9h2.3M31.7 85.4h7"/>
<path d="M37.1 81.7h1.6M40.6 94.2l-1.9 1.9h-9.2M40.6 97.9l-1.9 1.9h-9.2M40.6 96.1l-1.9 1.8h-9.2M44.8 96.7v6.8M46.1 86.8h-33.3v9.3h4.1M59.5 81.2h-4.1v3.7h-5.5M73.6 81.2h9.6l1.9 1.9M86.8 97.9v4M90.6 81.2l1.9 1.9h27.8M90.6 83.1l1.9 1.8h27.8M90.6 84.9l1.9 1.9h27.8"/>
<path d="M94.4 94.2l1.8 1.9h24.1M94.4 92.4l1.8 1.8h24.1M94.4 90.5l1.8 1.9h24.1M94.4 88.6l1.8 1.9h24.1M107.1 96.5h7.6M107.5 98.3h7.2M118.9 99.8h-19l-1.8 1.8M118.9 97.9h-19l-1.8 1.9M122 99.1h2.2M122 97.2h2.5M144.4 81.2l-1.8 1.9h-11.2M144.4 83.1l-1.8 1.8h-11.2"/>
<path d="M144.4 84.9l-1.8 1.9h-11.2M287.2 86.4h2.7M14.6 109h2.3M14.6 107.2h2.3M14.6 105.3h2.3M14.6 103.5h2.3M14.6 101.6h2.3M31.3 109.5h7.2M40.6 112.8l1.8 1.8h16.7M40.6 105.3l-1.9 1.9h-7.8M40.6 103.5l-1.9 1.8h-9.2M47.5 116.9h4.2"/>
<path d="M53.6 109v3.8h5.5M71.7 112.8h2.3M71.7 116.5h2.3M75.8 113.2h7.2M75.8 116.9h7.2M85.1 112.8l-1.9 1.8h-11.5M85.1 116.5l-1.9 1.8h-11.5M90.6 107.2l1.9 1.8h27.8M90.6 109l1.9 1.9h27.8M90.6 110.9l1.9 1.9h27.8M90.6 112.8l1.9 1.8h27.8M94.4 116.5l1.8 1.8h24.1"/>
<path d="M94.4 118.3l1.8 1.9h24.1M144.4 107.2l-1.8 1.8h-11.2M144.4 109l-1.8 1.9h-11.2M144.4 110.9l-1.8 1.9h-11.2M144.4 112.8l-1.8 1.8h-11.2M153.7 107.2l1.8 1.8h14.9M153.7 109l1.8 1.9h14.9M153.7 110.9l1.8 1.9h14.9M153.7 112.8l1.8 1.8h14.9M153.7 114.6l1.8 1.9h14.9M153.7 116.5l1.8 1.8h14.9M153.7 118.3l1.8 1.9h14.9"/>
<path d="M181.5 109h16.7l1.8 1.9 1.9-1.9h13M181.5 110.9h16.7l1.8 1.9 1.9-1.9h13M181.5 112.8h16.7l1.8 1.8 1.9-1.8h13M181.5 114.6h16.7l1.8 1.9 1.9-1.9h13M181.5 116.5h16.7l1.8 1.8 1.9-1.8h13M181.5 118.3h16.7l1.8 1.9 1.9-1.9h13M226 109h13.9M226 110.9h13.9M226 112.8h13.9M226 114.6h13.9M226 116.5h13.9M226 118.3h13.9"/>
<path d="M253.8 109h4.6v20.4M253.8 110.9h4.6M253.8 112.8h4.6M253.8 114.6h4.6M253.8 116.5h4.6M253.8 118.3h4.6M7.2 123.3h2.8M74 139.1h8.1M75.8 131.7h7.6M85.1 131.3l-1.9 1.8h-40.8v14.9h16.7M90.6 133.1l-1.8 1.9h-44.5v9.3h14.8M90.6 136.8l1.9 1.9h27.8"/>
<path d="M90.6 138.7l1.9 1.8h27.8M90.6 135l1.9 1.8h27.8M94.4 120.2l1.8 1.8h24.1M94.4 122l1.8 1.9h24.1M107.1 124.3h7.6M107.5 126.1h7.2M118.9 125.7h-19l-1.8 1.9M118.9 127.6h-19l-1.8 1.8M122 126.9h2.2M122 125h2.5M144.4 136.8l-1.8 1.9h-11.2M144.4 138.7l-1.8 1.8h-11.2"/>
<path d="M144.4 135l-1.8 1.8h-11.2M153.7 120.2l1.8 1.8h14.9M168.9 125.7h-7.8v39h-79.7v-22.3h-11.1M168.9 127.6h-4.1v3.7M181.5 120.2h16.7l1.8 1.8 1.9-1.8h13M181.5 122h16.7l1.8 1.9 1.9-1.9h13M209.3 127.6h4.1M212.9 136.1h6.4M213.4 125.7h-4.1v5.6M226 120.2h13.9M226 122h13.9M231.5 124.4h6"/>
<path d="M239.9 125.7h-10.2v11.1h-9.3M239.9 123.9h-12.1v43.5M253.8 125.7h4.6M253.8 120.2h4.6M253.8 122h4.6M253.8 123.9h4.6M287.2 123.3h2.7M15.2 141.6h6.1M23.9 142.4h33.8M40.6 146.1v3.7h17.1M46 146.5h7.6M47.5 141h6.1"/>
<path d="M53.6 155.4v3.7h4.1M59.1 147.3l1.5 .7-1.5 .7M67.3 149.1h1.2M70.3 149.8h7.4v17.6h194.6M70.3 159.1h3.7M90.6 140.5l1.9 1.9h27.8M94.4 148l1.8 1.8h24.1M94.4 146.1l1.8 1.9h24.1M94.4 149.8l1.8 1.9h24.1M94.4 144.3l1.8 1.8h24.1M107.1 152.1h7.6M107.5 153.9h7.2"/>
<path d="M118.9 155.4h-19l-1.8 1.8M118.9 153.5h-19l-1.8 1.9M122 154.7h2.2M122 152.8h2.5M144.4 140.5l-1.8 1.9h-11.2M227.8 159.1h10M240.2 159.1h8M251.9 159.1h11.2v3.7M7.2 160.2h2.8M22.1 179.5v4.1M31.3 179.5v4.1M36.9 179.5v4.1"/>
<path d="M42.4 179.5v4.1M48 179.5v4.1M53.6 166.5h4.1M53.6 164.7h5.5M53.6 179.5v4.1M59.1 161h-5.5v9.2M59.1 163.9l1.5 .8-1.5 .7M59.1 179.5v4.1M64.7 179.5v4.1M67.3 165.8h1.2M70.3 166.5h3.7M70.3 179.5v4.1"/>
<path d="M75.8 179.5v4.1M86.9 175.8v7.8M86.9 179.5h-70.4v4.1M145.5 163.2h8.2M258.1 160.6l1 1M258.4 161.3l.7 .3M258.4 161.3l.4-.3 .3 .6M258.4 161.3h.6M258.5 161.2h.4M258.6 161.2h.3M258.6 161.4h.4M258.7 161.1h.2"/>
<path d="M258.7 161h.1M258.8 161.5h.2M258.9 160.5l1 1M259 161.6h.1M259.3 161.2h.5M259.4 161.1h.3M259.5 161h.2M259.5 161.3h.3M259.5 160.9h.2M259.6 160.8l.3 .7-.6-.3zM259.7 161.4h.2M259.9 161.5h.1"/>
<path d="M287.2 160.2h2.7M16.5 184.7v7.8M22.1 184.7v4.1M31.3 184.7v4.1M36.9 184.7v4.1M42.4 184.7v4.1M44.6 197.1v2.8M48 184.7v4.1M53.6 184.7v4.1M59.1 184.7v4.1M64.7 184.7v4.1M70.3 184.7v4.1"/>
<path d="M75.8 184.7v4.1M79.3 197.1v2.8M86.9 184.7v4.1h-70.4M113.9 197.1v2.8M148.6 197.1v2.8M183.2 197.1v2.8M217.9 197.1v2.8M252.5 197.1v2.8M287.2 197h.1"/>
<circle cx="60.3" cy="64.6" r=".72"/>
<circle cx="60.3" cy="62.7" r=".72"/>
<circle cx="72.8" cy="79.4" r=".72"/>
<circle cx="72.8" cy="75.7" r=".72"/>
<circle cx="72.8" cy="77.5" r=".72"/>
<circle cx="119.6" cy="70.1" r=".72"/>
<circle cx="119.6" cy="72" r=".72"/>
<circle cx="199.3" cy="70.1" r=".72"/>
<circle cx="199.3" cy="72" r=".72"/>
<circle cx="17.6" cy="97.9" r=".72"/>
<circle cx="17.6" cy="99.8" r=".72"/>
<circle cx="17.6" cy="96.1" r=".72"/>
<circle cx="60.3" cy="81.2" r=".72"/>
<circle cx="72.8" cy="81.2" r=".72"/>
<circle cx="119.6" cy="97.9" r=".72"/>
<circle cx="119.6" cy="99.8" r=".72"/>
<circle cx="17.6" cy="105.3" r=".72"/>
<circle cx="17.6" cy="107.2" r=".72"/>
<circle cx="17.6" cy="109" r=".72"/>
<circle cx="17.6" cy="101.6" r=".72"/>
<circle cx="17.6" cy="103.5" r=".72"/>
<circle cx="30.2" cy="109" r=".72"/>
<circle cx="30.2" cy="107.2" r=".72"/>
<circle cx="58.4" cy="118.3" r=".72"/>
<circle cx="71" cy="118.3" r=".72"/>
<circle cx="71" cy="112.8" r=".72"/>
<circle cx="71" cy="116.5" r=".72"/>
<circle cx="71" cy="114.6" r=".72"/>
<circle cx="119.6" cy="127.6" r=".72"/>
<circle cx="119.6" cy="125.7" r=".72"/>
<circle cx="169.7" cy="125.7" r=".72"/>
<circle cx="169.7" cy="127.6" r=".72"/>
<circle cx="214.1" cy="125.7" r=".72"/>
<circle cx="214.1" cy="127.6" r=".72"/>
<circle cx="58.4" cy="142.4" r=".72"/>
<circle cx="58.4" cy="159.1" r=".72"/>
<circle cx="58.4" cy="149.8" r=".72"/>
<circle cx="119.6" cy="153.5" r=".72"/>
<circle cx="119.6" cy="155.4" r=".72"/>
<circle cx="58.4" cy="166.5" r=".72"/>
</g>
<g fill="none" stroke="#000" stroke-width=".19">
<path d="M13.3 33.8h9.5l1.1 1.1-1.1 1.1h-9.5zM14.5 22.6h8.3l1.1 1.2-1.1 1.1h-8.3zM16.4 26.4h6.4l1.1 1.1-1.1 1.1h-6.4zM18.9 30.1h3.9l1.1 1.1-1.1 1.1h-3.9zM52.6 40l1-1.4 .9 1.4M162.2 30.1h3.9v2.2h-3.9l-1.1-1.1zM162.2 22.6h8.3v2.3h-8.3l-1.1-1.1zM162.2 33.8h9.5v2.2h-9.5l-1.1-1.1zM256.8 26.4h6.4v2.2h-6.4l-1.1-1.1zM13.9 59.7h7l1.2 1.1-1.2 1.2h-7zM23 49.3l.9-1.4 .9 1.4M23.3 53.4h1.3v3.7h-1.3z"/>
<path d="M54 68.3h2.8M54.5 73.4l.9-1.4 .9 1.4M193.1 75.7h2.8M52.6 110.4l1-1.4 .9 1.4M163.4 131.3h2.8M207.9 131.3h2.8M212.3 135.7h7l1.1 1.1-1.1 1.2h-7zM257 129.4h2.8M14.5 141.3h8.3l1.1 1.1-1.1 1.1h-8.3zM39.7 147.5l.9-1.4 .9 1.4M52.6 156.8l1-1.4 .9 1.4M248.2 158.5h3.7v1.2h-3.7z"/>
<path d="M257.5 158.2l1.9 .9-1.9 .9zM257.5 159.9h.2M257.5 159.8h.5M257.5 159.6h.8M257.5 159.5h1.1M257.5 159.3h1.4M257.5 159.2h1.7M257.5 159h1.7M257.5 158.9h1.4M257.5 158.7h1.1M257.5 158.6h.8M257.5 158.4h.5"/>
<path d="M257.5 158.2h.2M259.4 158.2v1.8M52.2 170.2h2.7M86 177.2l.9-1.4 1 1.4M224.1 178.6h63.1M261.7 162.8h2.8M272.3 167.4l1.2-1.1h8.8v2.3h-8.8zM15.1 192.5h2.8M224.1 182.3h63.1M224.1 186h63.1M224.1 189.7h63.1M266.8 186v3.7"/>
<path d="M287.2 192.5v.9h-63.1"/>
</g>
<g fill="none" stroke="#000" stroke-width=".47">
<path d="M10 12.6h277.2v184.5h-277.2zM61 38.6h11.1v27.8h-11.1zM120.3 51.6h11.1v22.2h-11.1zM200 51.6h11.2v22.2h-11.2zM61 73.8h11.1v9.3h-11.1zM120.3 79.4h11.1v22.2h-11.1zM18.4 94.2h11.1v16.7h-11.1zM46.1 81.2a3.7 3.7 0 0 1 3.8 3.7 3.7 3.7 0 0 1-3.8 3.7zM59.1 110.9h11.2v9.3h-11.2zM120.3 107.2h11.1v22.2h-11.1zM170.4 107.2h11.1v22.2h-11.1zM214.9 107.2h11.1v22.2h-11.1z"/>
<path d="M239.9 110.9h.9M239.9 109h.9M239.9 112.8h.9M239.9 114.6h.9M239.9 116.5h.9M239.9 118.3h.9M252.9 110.9h.9M252.9 109h.9M252.9 112.8h.9M252.9 114.6h.9M252.9 116.5h.9M252.9 118.3h.9"/>
<path d="M120.3 135h11.1v22.2h-11.1zM239.9 120.2h.9M239.9 122h.9M239.9 123.9h.9M239.9 125.7h.9M252.9 120.2h.9M252.9 122h.9M252.9 123.9h.9M252.9 125.7h.9M59.1 140.5h11.2v11.2h-11.2zM59.1 157.2h11.2v11.2h-11.2zM224.1 174.9v22.2"/>
<path d="M287.2 174.9h-85.3v22.2"/>
</g>
<path d="M7.2 9.9h282.7v190h-282.7z" fill="none" stroke="#000" stroke-width=".23"/>
<g fill="#000" stroke="#000" stroke-width=".16">
<path d="M259.2 158h.3v2.2h-.3zM15 183.6h3v.3h-3zM15 184.3h3v.4h-3zM20.6 183.6h2.9v.3h-2.9zM20.6 184.3h2.9v.4h-2.9zM29.8 183.6h3v.3h-3zM29.8 184.3h3v.4h-3zM35.4 183.6h3v.3h-3zM35.4 184.3h3v.4h-3zM41 183.6h2.9v.3h-2.9zM41 184.3h2.9v.4h-2.9zM46.5 183.6h3v.3h-3z"/>
<path d="M46.5 184.3h3v.4h-3zM52.1 183.6h3v.3h-3zM52.1 184.3h3v.4h-3zM57.6 183.6h3v.3h-3zM57.6 184.3h3v.4h-3zM63.2 183.6h3v.3h-3zM63.2 184.3h3v.4h-3zM68.8 183.6h2.9v.3h-2.9zM68.8 184.3h2.9v.4h-2.9zM74.3 183.6h3v.3h-3zM74.3 184.3h3v.4h-3zM85.4 183.6h3v.3h-3z"/>
<path d="M85.4 184.3h3v.4h-3z"/>
</g>
<g fill="#000" stroke="#000" stroke-width=".16">
<path d="M238.1 158.4l.6-.2v1.8a.93 .93 0 0 1-.9-.6 .93 .93 0 0 1 .3-1z" fill-rule="evenodd"/>
<path d="M239.2 158.2a.93 .93 0 0 1 1 .9 .93 .93 0 0 1-1 .9z" fill-rule="evenodd"/>
<circle cx="27.6" cy="31.2" r=".38"/>
<circle cx="31.3" cy="34.9" r=".38"/>
<circle cx="88.8" cy="27.5" r=".38"/>
<circle cx="183.3" cy="27.5" r=".38"/>
<circle cx="53.6" cy="42.3" r=".38"/>
<circle cx="55.4" cy="49.7" r=".38"/>
<circle cx="55.4" cy="46" r=".38"/>
<circle cx="55.4" cy="53.4" r=".38"/>
<circle cx="55.4" cy="44.2" r=".38"/>
<circle cx="55.4" cy="51.6" r=".38"/>
<circle cx="23.9" cy="60.8" r=".38"/>
<circle cx="55.4" cy="62.7" r=".38"/>
<circle cx="55.4" cy="64.6" r=".38"/>
<circle cx="194.5" cy="60.8" r=".38"/>
<circle cx="194.5" cy="64.6" r=".38"/>
<circle cx="194.5" cy="62.7" r=".38"/>
<circle cx="258.4" cy="114.6" r=".38"/>
<circle cx="258.4" cy="112.8" r=".38"/>
<circle cx="258.4" cy="118.3" r=".38"/>
<circle cx="258.4" cy="116.5" r=".38"/>
<circle cx="258.4" cy="110.9" r=".38"/>
<circle cx="209.3" cy="127.6" r=".38"/>
<circle cx="258.4" cy="120.2" r=".38"/>
<circle cx="258.4" cy="122" r=".38"/>
<circle cx="258.4" cy="125.7" r=".38"/>
<circle cx="258.4" cy="123.9" r=".38"/>
<circle cx="227.8" cy="159.1" r=".38"/>
<circle cx="22.1" cy="179.5" r=".38"/>
<circle cx="31.3" cy="179.5" r=".38"/>
<circle cx="36.9" cy="179.5" r=".38"/>
<circle cx="42.4" cy="179.5" r=".38"/>
<circle cx="48" cy="179.5" r=".38"/>
<circle cx="53.6" cy="179.5" r=".38"/>
<circle cx="53.6" cy="166.5" r=".38"/>
<circle cx="53.6" cy="164.7" r=".38"/>
<circle cx="59.1" cy="179.5" r=".38"/>
<circle cx="64.7" cy="179.5" r=".38"/>
<circle cx="70.3" cy="179.5" r=".38"/>
<circle cx="75.8" cy="179.5" r=".38"/>
<circle cx="86.9" cy="179.5" r=".38"/>
<circle cx="159.2" cy="167.4" r=".38"/>
<circle cx="227.8" cy="167.4" r=".38"/>
<circle cx="16.5" cy="188.8" r=".38"/>
<circle cx="22.1" cy="188.8" r=".38"/>
<circle cx="31.3" cy="188.8" r=".38"/>
<circle cx="36.9" cy="188.8" r=".38"/>
<circle cx="42.4" cy="188.8" r=".38"/>
<circle cx="48" cy="188.8" r=".38"/>
<circle cx="53.6" cy="188.8" r=".38"/>
<circle cx="59.1" cy="188.8" r=".38"/>
<circle cx="64.7" cy="188.8" r=".38"/>
<circle cx="70.3" cy="188.8" r=".38"/>
<circle cx="75.8" cy="188.8" r=".38"/>
</g>
<path d="M23.9 16.3h165M38.7 16.3l1.9 1.9v94.6M92.5 16.3l1.9 1.9v131.6M23.9 20.1h64.9l1.8 1.8v118.6M226 55.3v22.2l-1.9 1.9h-22.2l-1.9 1.8v55.6l3.7 3.7h68.6M98.1 72v89l-1.9 1.8h-9.3l-1.8-1.8v-81.6M153.7 120.2v-70.5l-1.9-1.8h-5.5l-1.9 1.8v90.8" fill="none" stroke="#000" stroke-width=".57"/>
<use href="#words"/>
</svg>
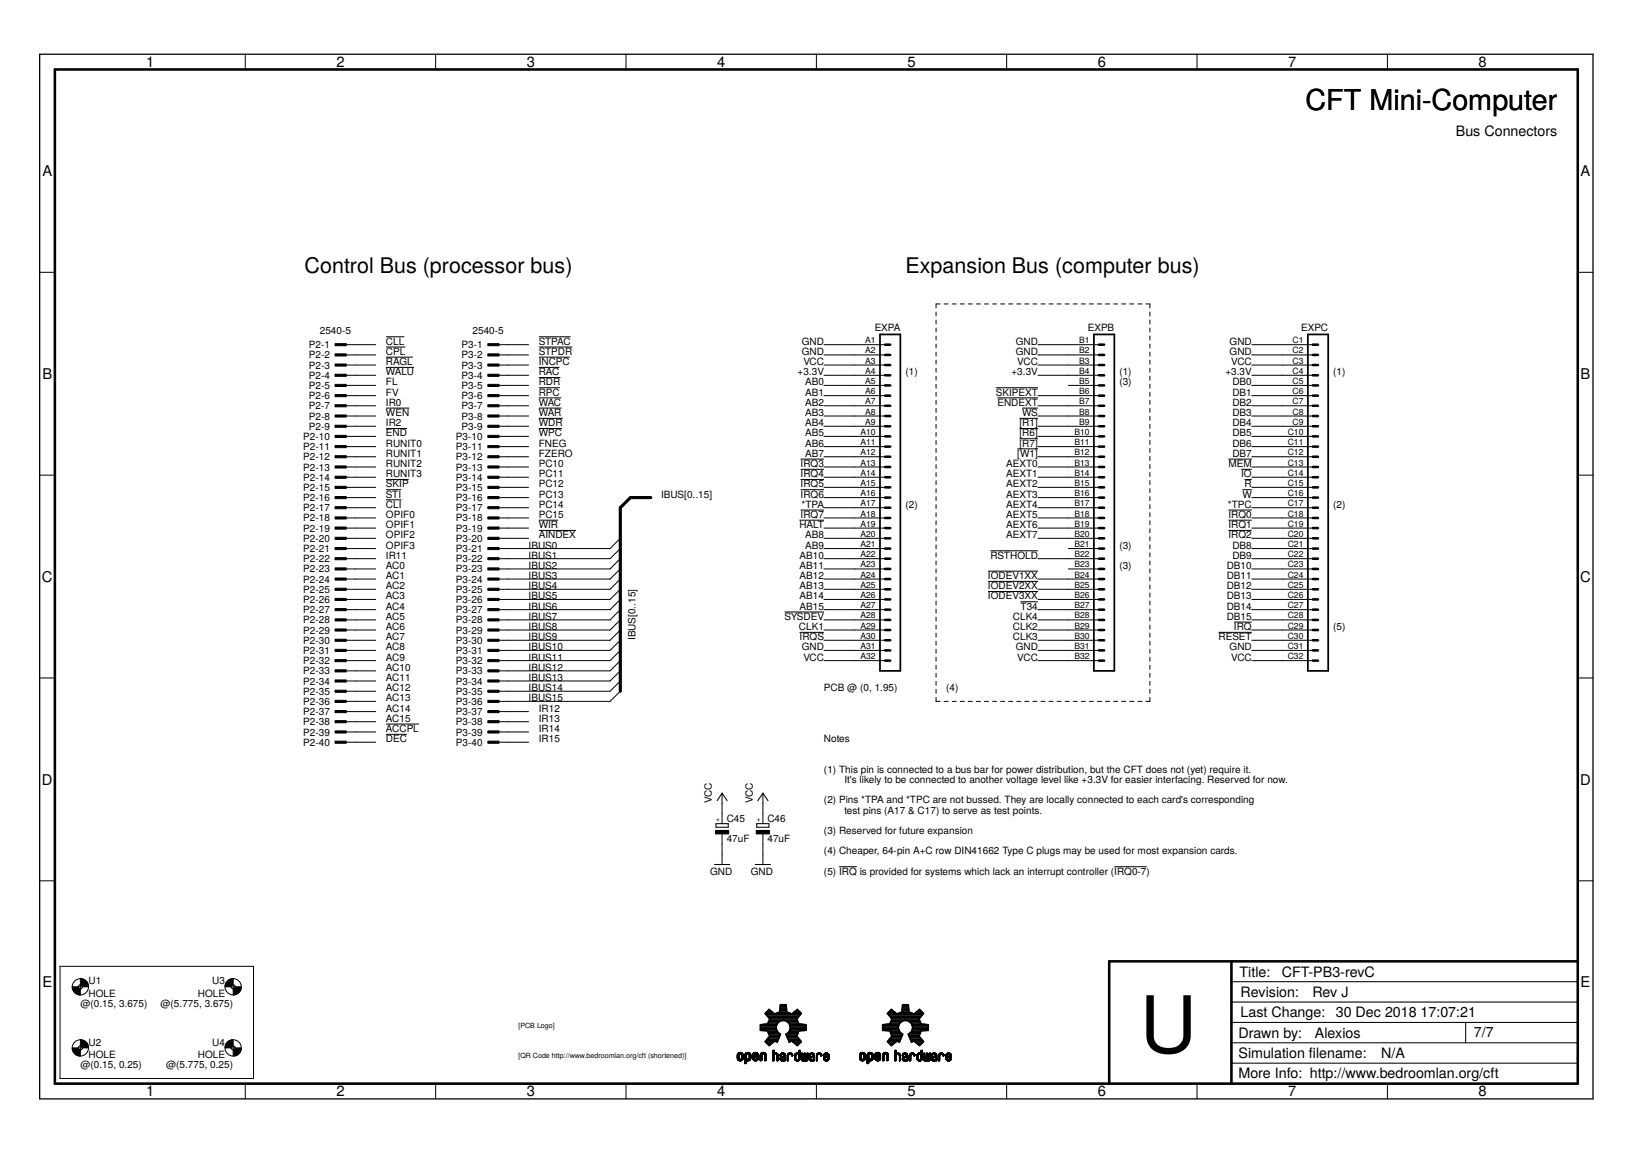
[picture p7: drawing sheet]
<svg xmlns="http://www.w3.org/2000/svg" width="297mm" height="210mm" viewBox="0 0 297 210" stroke-linecap="round" stroke-linejoin="round" font-family="sans-serif">
<defs><g id="words">
<text font-size="14.4" x="207.4" y="191.5">U</text>
<text font-size="5.2" x="237.6" y="20.1">CFT Mini-Computer</text>
<g font-size="3.9">
<text x="55.4" y="49.7">Control Bus (processor bus)</text>
<text x="164.8" y="49.7">Expansion Bus (computer bus)</text>
</g>
<g font-size="2.7">
<text x="26.6" y="12.2">1</text>
<text x="61.2" y="12.2">2</text>
<text x="95.9" y="12.2">3</text>
<text x="130.5" y="12.2">4</text>
<text x="165.2" y="12.2">5</text>
<text x="199.8" y="12.2">6</text>
<text x="234.5" y="12.2">7</text>
<text x="269.1" y="12.2">8</text>
<text x="7.7" y="32">A</text>
<text x="287.7" y="32">A</text>
<text x="7.7" y="68.9">B</text>
<text x="287.7" y="68.9">B</text>
<text x="7.6" y="105.8">C</text>
<text x="287.6" y="105.8">C</text>
<text x="7.6" y="142.7">D</text>
<text x="287.6" y="142.7">D</text>
<text x="7.7" y="179.6">E</text>
<text x="287.7" y="179.6">E</text>
<text x="26.6" y="199.4">1</text>
<text x="61.2" y="199.4">2</text>
<text x="95.9" y="199.4">3</text>
<text x="130.5" y="199.4">4</text>
<text x="165.2" y="199.4">5</text>
<text x="199.8" y="199.4">6</text>
<text x="234.5" y="199.4">7</text>
<text x="269.1" y="199.4">8</text>
</g>
<g font-size="2.6">
<text x="265" y="24.7">Bus Connectors</text>
<text x="225.6" y="177.6">Title:</text>
<text x="233.3" y="177.7">CFT-PB3-revC</text>
<text x="225.8" y="181.3">Revision:</text>
<text x="225.8" y="185">Last Change:</text>
<text x="238.9" y="181.4">Rev J</text>
<text x="243.1" y="185">30 Dec 2018</text>
<text x="258.6" y="185">17:07:21</text>
<text x="225.4" y="188.8">Drawn by:</text>
<text x="239.3" y="188.8">Alexios</text>
<text x="268.3" y="188.7">7/7</text>
<text x="225.4" y="192.5">Simulation flename:</text>
<text x="225.4" y="196.2">More Info: http://www.bedroomlan.org/cft</text>
<text x="238.2" y="192.5">i</text>
<text x="251.4" y="192.5">N/A</text>
</g>
<g font-size="1.8">
<text x="56.2" y="63.3">P2-1</text>
<text x="56.2" y="65.2">P2-2</text>
<text x="58.2" y="60.7">2540-5</text>
<text x="70.3" y="62.7">CLL</text>
<text x="70.3" y="64.5">CPL</text>
<text x="84" y="63.3">P3-1</text>
<text x="84" y="65.2">P3-2</text>
<text x="86" y="60.7">2540-5</text>
<text x="98.1" y="64.5">STPDR</text>
<text x="98.1" y="62.7">STPAC</text>
<text x="145.9" y="64.5">GND</text>
<text x="145.9" y="62.7">GND</text>
<text x="159.2" y="60.3">EXPA</text>
<text x="184.9" y="64.5">GND</text>
<text x="184.9" y="62.7">GND</text>
<text x="198" y="60.3">EXPB</text>
<text x="223.8" y="64.5">GND</text>
<text x="223.8" y="62.7">GND</text>
<text x="236.8" y="60.3">EXPC</text>
<text x="56.2" y="67">P2-3</text>
<text x="56.2" y="68.9">P2-4</text>
<text x="56.2" y="70.8">P2-5</text>
<text x="70.3" y="72">FV</text>
<text x="70.3" y="70.1">FL</text>
<text x="70.3" y="68.3">WALU</text>
<text x="70.3" y="66.4">RAGL</text>
<text x="84" y="67">P3-3</text>
<text x="84" y="68.9">P3-4</text>
<text x="84" y="70.8">P3-5</text>
<text x="98.1" y="66.4">INCPC</text>
<text x="98.1" y="72">RPC</text>
<text x="98.1" y="70.1">RDR</text>
<text x="98.1" y="68.3">RAC</text>
<text x="145.2" y="68.3">+3.3V</text>
<text x="146.2" y="66.4">VCC</text>
<text x="146.5" y="72">AB1</text>
<text x="146.5" y="70.1">AB0</text>
<text x="164.8" y="68.3">(1)</text>
<text x="181.2" y="72">SKIPEXT</text>
<text x="184.1" y="68.3">+3.3V</text>
<text x="185.2" y="66.4">VCC</text>
<text x="203.7" y="68.3">(1)</text>
<text x="203.7" y="70.1">(3)</text>
<text x="223" y="68.3">+3.3V</text>
<text x="224.1" y="66.4">VCC</text>
<text x="224.3" y="72">DB1</text>
<text x="224.3" y="70.1">DB0</text>
<text x="242.7" y="68.3">(1)</text>
<text x="56.2" y="72.6">P2-6</text>
<text x="56.2" y="74.5">P2-7</text>
<text x="56.2" y="76.3">P2-8</text>
<text x="70.3" y="73.8">IR0</text>
<text x="70.3" y="77.5">IR2</text>
<text x="70.3" y="75.7">WEN</text>
<text x="84" y="72.6">P3-6</text>
<text x="84" y="74.5">P3-7</text>
<text x="84" y="76.3">P3-8</text>
<text x="98.1" y="75.7">WAR</text>
<text x="98.1" y="77.5">WDR</text>
<text x="98.1" y="73.8">WAC</text>
<text x="146.5" y="77.5">AB4</text>
<text x="146.5" y="75.7">AB3</text>
<text x="146.5" y="73.8">AB2</text>
<text x="181.5" y="73.8">ENDEXT</text>
<text x="185.6" y="77.5">[R1]</text>
<text x="186" y="75.7">WS</text>
<text x="224.3" y="77.5">DB4</text>
<text x="224.3" y="75.7">DB3</text>
<text x="224.3" y="73.8">DB2</text>
<text x="55.2" y="80">P2-10</text>
<text x="55.2" y="81.9">P2-11</text>
<text x="55.2" y="83.7">P2-12</text>
<text x="56.2" y="78.2">P2-9</text>
<text x="70.3" y="81.2">RUNIT0</text>
<text x="70.3" y="83.1">RUNIT1</text>
<text x="70.3" y="79.4">END</text>
<text x="83" y="80">P3-10</text>
<text x="83" y="81.9">P3-11</text>
<text x="83" y="83.7">P3-12</text>
<text x="84" y="78.2">P3-9</text>
<text x="98.1" y="81.2">FNEG</text>
<text x="98.1" y="83.1">FZERO</text>
<text x="98.1" y="79.4">WPC</text>
<text x="146.5" y="83.1">AB7</text>
<text x="146.5" y="81.2">AB6</text>
<text x="146.5" y="79.4">AB5</text>
<text x="185.2" y="83.1">[W1]</text>
<text x="185.6" y="79.4">[R6]</text>
<text x="185.6" y="81.2">[R7]</text>
<text x="224.3" y="83.1">DB7</text>
<text x="224.3" y="81.2">DB6</text>
<text x="224.3" y="79.4">DB5</text>
<text x="55.2" y="85.6">P2-13</text>
<text x="55.2" y="87.4">P2-14</text>
<text x="55.2" y="89.3">P2-15</text>
<text x="70.3" y="84.9">RUNIT2</text>
<text x="70.3" y="86.8">RUNIT3</text>
<text x="70.3" y="88.6">SKIP</text>
<text x="83" y="85.6">P3-13</text>
<text x="83" y="87.4">P3-14</text>
<text x="83" y="89.3">P3-15</text>
<text x="98.1" y="84.9">PC10</text>
<text x="98.1" y="86.8">PC11</text>
<text x="98.1" y="88.6">PC12</text>
<text x="145.7" y="84.9">IRQ3</text>
<text x="145.7" y="86.8">IRQ4</text>
<text x="145.7" y="88.6">IRQ5</text>
<text x="183.1" y="88.6">AEXT2</text>
<text x="183.1" y="86.8">AEXT1</text>
<text x="183.1" y="84.9">AEXT0</text>
<text x="223.6" y="84.9">MEM</text>
<text x="225.9" y="86.8">IO</text>
<text x="226.5" y="88.6">R</text>
<text x="55.2" y="91.1">P2-16</text>
<text x="55.2" y="93">P2-17</text>
<text x="55.2" y="94.9">P2-18</text>
<text x="70.3" y="94.2">OPIF0</text>
<text x="70.3" y="90.5">STI</text>
<text x="70.3" y="92.4">CLI</text>
<text x="83" y="91.1">P3-16</text>
<text x="83" y="93">P3-17</text>
<text x="83" y="94.9">P3-18</text>
<text x="98.1" y="90.5">PC13</text>
<text x="98.1" y="92.4">PC14</text>
<text x="98.1" y="94.2">PC15</text>
<text x="120.3" y="90.5">IBUS[0..15]</text>
<text x="145.7" y="94.2">IRQ7</text>
<text x="145.7" y="90.5">IRQ6</text>
<text x="145.9" y="92.4">*TPA</text>
<text x="164.8" y="92.4">(2)</text>
<text x="183.1" y="94.2">AEXT5</text>
<text x="183.1" y="92.4">AEXT4</text>
<text x="183.1" y="90.5">AEXT3</text>
<text x="223.5" y="92.4">*TPC</text>
<text x="223.6" y="94.2">IRQ0</text>
<text x="226.1" y="90.5">W</text>
<text x="242.7" y="92.4">(2)</text>
<text x="55.2" y="96.7">P2-19</text>
<text x="55.2" y="98.6">P2-20</text>
<text x="55.2" y="100.4">P2-21</text>
<text x="70.3" y="96.1">OPIF1</text>
<text x="70.3" y="97.9">OPIF2</text>
<text x="70.3" y="99.8">OPIF3</text>
<text x="70.3" y="101.6">IR11</text>
<text x="83" y="96.7">P3-19</text>
<text x="83" y="98.6">P3-20</text>
<text x="83" y="100.4">P3-21</text>
<text x="96.2" y="99.8">IBUS0</text>
<text x="96.2" y="101.6">IBUS1</text>
<text x="98.1" y="96.1">WIR</text>
<text x="98.1" y="97.9">AINDEX</text>
<text x="145.5" y="96.1">HALT</text>
<text x="145.5" y="101.6">AB10</text>
<text x="146.5" y="99.8">AB9</text>
<text x="146.5" y="97.9">AB8</text>
<text x="180.3" y="101.6">RSTHOLD</text>
<text x="183.1" y="97.9">AEXT7</text>
<text x="183.1" y="96.1">AEXT6</text>
<text x="203.7" y="99.8">(3)</text>
<text x="223.6" y="97.9">IRQ2</text>
<text x="223.6" y="96.1">IRQ1</text>
<text x="224.3" y="101.6">DB9</text>
<text x="224.3" y="99.8">DB8</text>
<text x="55.2" y="102.3">P2-22</text>
<text x="55.2" y="104.1">P2-23</text>
<text x="55.2" y="106">P2-24</text>
<text x="55.2" y="107.8">P2-25</text>
<text x="70.3" y="103.5">AC0</text>
<text x="70.3" y="105.3">AC1</text>
<text x="70.3" y="107.2">AC2</text>
<text x="83" y="102.3">P3-22</text>
<text x="83" y="104.1">P3-23</text>
<text x="83" y="106">P3-24</text>
<text x="83" y="107.8">P3-25</text>
<text x="96.2" y="103.5">IBUS2</text>
<text x="96.2" y="105.3">IBUS3</text>
<text x="96.2" y="107.2">IBUS4</text>
<text x="145.5" y="107.2">AB13</text>
<text x="145.5" y="105.3">AB12</text>
<text x="145.5" y="103.5">AB11</text>
<text x="179.8" y="107.2">IODEV2XX</text>
<text x="179.8" y="105.3">IODEV1XX</text>
<text x="203.7" y="103.5">(3)</text>
<text x="223.3" y="107.2">DB12</text>
<text x="223.3" y="105.3">DB11</text>
<text x="223.3" y="103.5">DB10</text>
<text x="55.2" y="109.7">P2-26</text>
<text x="55.2" y="111.5">P2-27</text>
<text x="55.2" y="113.4">P2-28</text>
<text x="70.3" y="109">AC3</text>
<text x="70.3" y="110.9">AC4</text>
<text x="70.3" y="112.7">AC5</text>
<text x="83" y="109.7">P3-26</text>
<text x="83" y="111.5">P3-27</text>
<text x="83" y="113.4">P3-28</text>
<text x="96.2" y="109">IBUS5</text>
<text x="96.2" y="112.7">IBUS7</text>
<text x="96.2" y="110.9">IBUS6</text>
<text x="142.8" y="112.7">SYSDEV</text>
<text x="145.5" y="110.9">AB15</text>
<text x="145.5" y="109">AB14</text>
<text x="179.8" y="109">IODEV3XX</text>
<text x="184.4" y="112.7">CLK4</text>
<text x="185.8" y="110.9">T34</text>
<text x="223.3" y="112.7">DB15</text>
<text x="223.3" y="110.9">DB14</text>
<text x="223.3" y="109">DB13</text>
<text x="55.2" y="115.2">P2-29</text>
<text x="55.2" y="117.1">P2-30</text>
<text x="55.2" y="119">P2-31</text>
<text x="70.3" y="114.6">AC6</text>
<text x="70.3" y="116.5">AC7</text>
<text x="70.3" y="118.3">AC8</text>
<text x="83" y="115.2">P3-29</text>
<text x="83" y="117.1">P3-30</text>
<text x="83" y="119">P3-31</text>
<text x="96.2" y="114.6">IBUS8</text>
<text x="96.2" y="116.5">IBUS9</text>
<text x="96.2" y="118.3">IBUS10</text>
<text x="115.7" y="116.5" transform="rotate(-90 115.7 116.5)">IBUS[0..15]</text>
<text x="145.4" y="114.6">CLK1</text>
<text x="145.5" y="116.5">IRQS</text>
<text x="145.9" y="118.3">GND</text>
<text x="184.4" y="114.6">CLK2</text>
<text x="184.4" y="116.5">CLK3</text>
<text x="184.9" y="118.3">GND</text>
<text x="221.8" y="116.5">RESET</text>
<text x="223.8" y="118.3">GND</text>
<text x="224.6" y="114.6">IRQ</text>
<text x="242.7" y="114.6">(5)</text>
<text x="55.2" y="120.8">P2-32</text>
<text x="55.2" y="122.7">P2-33</text>
<text x="55.2" y="124.5">P2-34</text>
<text x="70.3" y="125.7">AC12</text>
<text x="70.3" y="120.2">AC9</text>
<text x="70.3" y="122">AC10</text>
<text x="70.3" y="123.9">AC11</text>
<text x="83" y="120.8">P3-32</text>
<text x="83" y="122.7">P3-33</text>
<text x="83" y="124.5">P3-34</text>
<text x="96.2" y="120.2">IBUS11</text>
<text x="96.2" y="122">IBUS12</text>
<text x="96.2" y="123.9">IBUS13</text>
<text x="96.2" y="125.7">IBUS14</text>
<text x="146.2" y="120.2">VCC</text>
<text x="150" y="125.7">PCB @ (0, 1.95)</text>
<text x="172.2" y="125.7">(4)</text>
<text x="185.2" y="120.2">VCC</text>
<text x="224.1" y="120.2">VCC</text>
<text x="55.2" y="126.4">P2-35</text>
<text x="55.2" y="128.2">P2-36</text>
<text x="55.2" y="130.1">P2-37</text>
<text x="55.2" y="131.9">P2-38</text>
<text x="70.3" y="127.6">AC13</text>
<text x="70.3" y="129.4">AC14</text>
<text x="70.3" y="131.3">AC15</text>
<text x="83" y="126.4">P3-35</text>
<text x="83" y="128.2">P3-36</text>
<text x="83" y="130.1">P3-37</text>
<text x="83" y="131.9">P3-38</text>
<text x="96.2" y="127.6">IBUS15</text>
<text x="98.1" y="129.4">IR12</text>
<text x="98.1" y="131.3">IR13</text>
<text x="55.2" y="133.8">P2-39</text>
<text x="55.2" y="135.6">P2-40</text>
<text x="70.3" y="135">DEC</text>
<text x="70.3" y="133.1">ACCPL</text>
<text x="83" y="133.8">P3-39</text>
<text x="83" y="135.6">P3-40</text>
<text x="98.1" y="133.1">IR14</text>
<text x="98.1" y="135">IR15</text>
<text x="150" y="135">Notes</text>
<text x="150" y="140.6">(1) This pin is connected to a bus bar for power distribution, but the CFT does not (yet) require it.</text>
<text x="153.7" y="142.4">It's likely to be connected to another voltage level like +3.3V for easier interfacing. Reserved for now.</text>
<text x="129.6" y="146.1" transform="rotate(-90 129.6 146.1)">VCC</text>
<text x="132.3" y="149.5">C45</text>
<text x="137" y="146.1" transform="rotate(-90 137 146.1)">VCC</text>
<text x="139.7" y="149.5">C46</text>
<text x="150" y="146.1">(2) Pins *TPA and *TPC are not bussed. They are locally connected to each card's corresponding</text>
<text x="153.7" y="148">test pins (A17 &amp; C17) to serve as test points.</text>
<text x="132.3" y="153.2">47uF</text>
<text x="139.7" y="153.2">47uF</text>
<text x="150" y="151.7">(3) Reserved for future expansion</text>
<text x="150" y="155.4">(4) Cheaper, 64-pin A+C row DIN41662 Type C plugs may be used for most expansion cards.</text>
<text x="129.2" y="159.1">GND</text>
<text x="136.7" y="159.1">GND</text>
<text x="150" y="159.1">(5) IRQ is provided for systems which lack an interrupt controller (IRQ0-7)</text>
<text x="16.1" y="179.1">U1</text>
<text x="38.6" y="179.1">U3</text>
<text x="14.6" y="183.2">@(0.15, 3.675)</text>
<text x="16.1" y="181.3">HOLE</text>
<text x="29.2" y="183.2">@(5.775, 3.675)</text>
<text x="36" y="181.3">HOLE</text>
<text x="16.1" y="190.2">U2</text>
<text x="38.6" y="190.2">U4</text>
<text x="14.6" y="194.3">@(0.15, 0.25)</text>
<text x="16.1" y="192.4">HOLE</text>
<text x="30.2" y="194.3">@(5.775, 0.25)</text>
<text x="36" y="192.4">HOLE</text>
</g>
<g font-size="1.6">
<text x="157.5" y="62.4">A1</text>
<text x="157.5" y="64.3">A2</text>
<text x="196.4" y="62.4">B1</text>
<text x="196.4" y="64.3">B2</text>
<text x="235.3" y="62.4">C1</text>
<text x="235.3" y="64.3">C2</text>
<text x="157.5" y="66.1">A3</text>
<text x="157.5" y="68">A4</text>
<text x="157.5" y="69.9">A5</text>
<text x="157.5" y="71.7">A6</text>
<text x="196.4" y="66.1">B3</text>
<text x="196.4" y="68">B4</text>
<text x="196.4" y="69.9">B5</text>
<text x="196.4" y="71.7">B6</text>
<text x="235.3" y="66.1">C3</text>
<text x="235.3" y="68">C4</text>
<text x="235.3" y="69.9">C5</text>
<text x="235.3" y="71.7">C6</text>
<text x="157.5" y="73.6">A7</text>
<text x="157.5" y="75.4">A8</text>
<text x="157.5" y="77.3">A9</text>
<text x="196.4" y="73.6">B7</text>
<text x="196.4" y="75.4">B8</text>
<text x="196.4" y="77.3">B9</text>
<text x="235.3" y="73.6">C7</text>
<text x="235.3" y="75.4">C8</text>
<text x="235.3" y="77.3">C9</text>
<text x="156.6" y="79.1">A10</text>
<text x="156.6" y="81">A11</text>
<text x="156.6" y="82.8">A12</text>
<text x="195.5" y="79.1">B10</text>
<text x="195.5" y="81">B11</text>
<text x="195.5" y="82.8">B12</text>
<text x="234.4" y="79.1">C10</text>
<text x="234.4" y="81">C11</text>
<text x="234.4" y="82.8">C12</text>
<text x="156.6" y="84.7">A13</text>
<text x="156.6" y="86.5">A14</text>
<text x="156.6" y="88.4">A15</text>
<text x="195.5" y="84.7">B13</text>
<text x="195.5" y="86.5">B14</text>
<text x="195.5" y="88.4">B15</text>
<text x="234.4" y="84.7">C13</text>
<text x="234.4" y="86.5">C14</text>
<text x="234.4" y="88.4">C15</text>
<text x="156.6" y="90.2">A16</text>
<text x="156.6" y="92.1">A17</text>
<text x="156.6" y="93.9">A18</text>
<text x="156.6" y="95.8">A19</text>
<text x="195.5" y="90.2">B16</text>
<text x="195.5" y="92.1">B17</text>
<text x="195.5" y="93.9">B18</text>
<text x="195.5" y="95.8">B19</text>
<text x="234.4" y="90.2">C16</text>
<text x="234.4" y="92.1">C17</text>
<text x="234.4" y="93.9">C18</text>
<text x="234.4" y="95.8">C19</text>
<text x="156.6" y="97.7">A20</text>
<text x="156.6" y="99.5">A21</text>
<text x="156.6" y="101.4">A22</text>
<text x="195.5" y="97.7">B20</text>
<text x="195.5" y="99.5">B21</text>
<text x="195.5" y="101.4">B22</text>
<text x="234.4" y="97.7">C20</text>
<text x="234.4" y="99.5">C21</text>
<text x="234.4" y="101.4">C22</text>
<text x="156.6" y="103.2">A23</text>
<text x="156.6" y="105.1">A24</text>
<text x="156.6" y="106.9">A25</text>
<text x="195.5" y="103.2">B23</text>
<text x="195.5" y="105.1">B24</text>
<text x="195.5" y="106.9">B25</text>
<text x="234.4" y="103.2">C23</text>
<text x="234.4" y="105.1">C24</text>
<text x="234.4" y="106.9">C25</text>
<text x="156.6" y="108.8">A26</text>
<text x="156.6" y="110.6">A27</text>
<text x="156.6" y="112.5">A28</text>
<text x="195.5" y="108.8">B26</text>
<text x="195.5" y="110.6">B27</text>
<text x="195.5" y="112.5">B28</text>
<text x="234.4" y="108.8">C26</text>
<text x="234.4" y="110.6">C27</text>
<text x="234.4" y="112.5">C28</text>
<text x="156.6" y="114.3">A29</text>
<text x="156.6" y="116.2">A30</text>
<text x="156.6" y="118">A31</text>
<text x="156.6" y="119.9">A32</text>
<text x="195.5" y="114.3">B29</text>
<text x="195.5" y="116.2">B30</text>
<text x="195.5" y="118">B31</text>
<text x="195.5" y="119.9">B32</text>
<text x="234.4" y="114.3">C29</text>
<text x="234.4" y="116.2">C30</text>
<text x="234.4" y="118">C31</text>
<text x="234.4" y="119.9">C32</text>
</g>
<g font-size="1.3">
<text x="131" y="149.5" transform="rotate(-90 131 149.5)">+</text>
<text x="138.4" y="149.5" transform="rotate(-90 138.4 149.5)">+</text>
<text x="94.4" y="186.9">[PCB Logo]</text>
<text x="94.4" y="192.5">[QR Code http://www.bedroomlan.org/cft (shortened)]</text>
</g>
</g></defs>
<g fill="none" stroke="#000" stroke-width=".18">
<path d="M10 12.6h277.2v184.5h-277.2zM44.6 9.9v2.7M79.3 9.9v2.7M113.9 9.9v2.7M148.6 9.9v2.7M183.2 9.9v2.7M217.9 9.9v2.7M252.5 9.9v2.7M7.2 49.5h2.8M170.4 56.7v.8M170.4 58.2v.7M170.4 59.7v.7"/>
<path d="M171.1 55.3h-.7v.7M171.8 55.3h.8M173.3 55.3h.7M174.8 55.3h.7M176.2 55.3h.8M177.7 55.3h.8M179.2 55.3h.7M180.7 55.3h.7M182.1 55.3h.8M183.6 55.3h.7M185.1 55.3h.7M186.5 55.3h.8"/>
<path d="M188 55.3h.7M189.5 55.3h.7M190.9 55.3h.8M192.4 55.3h.7M193.9 55.3h.7M195.3 55.3h.8M196.8 55.3h.7M198.3 55.3h.7M199.7 55.3h.8M201.2 55.3h.8M202.7 55.3h.7M204.2 55.3h.7"/>
<path d="M205.6 55.3h.8M207.1 55.3h.7M208.6 55.3h.7v.7M209.3 56.7v.8M209.3 58.2v.7M209.3 59.7v.7M287.2 49.5h2.7M62.8 62.7h5.6M62.8 64.6h5.6M62.8 66.4h5.6M62.8 68.3h5.6M62.8 70.1h5.6"/>
<path d="M62.8 72h5.6M62.8 73.8h5.6M62.8 75.7h5.6M62.8 77.5h5.6M62.8 79.4h5.6M70.3 74.2h4.2M70.3 63.1h3.5M70.3 65h4.8M70.3 61.3h3.3M70.3 66.8h5.1M70.3 77.9h3.8M90.6 62.7h5.6"/>
<path d="M90.6 64.6h5.6M90.6 66.4h5.6M90.6 68.3h5.6M90.6 70.1h5.6M90.6 72h5.6M90.6 73.8h5.6M90.6 75.7h5.6M90.6 77.5h5.6M90.6 79.4h5.6M98.1 70.5h3.8M98.1 72.4h4.1M98.1 74.2h4.1"/>
<path d="M98.1 63.1h6.1M98.1 65h5.6M98.1 61.3h5.8M98.1 68.7h3.9M98.1 66.8h3.7M98.1 77.9h4.2M98.1 76.1h4.3M150 62.7h11.1M150 64.6h11.1M150 66.4h11.1M150 68.3h11.1M150 70.1h11.1"/>
<path d="M150 72h11.1M150 73.8h11.1M150 75.7h11.1M150 77.5h11.1M150 79.4h11.1M170.4 61.1v.7M170.4 62.6v.7M170.4 64.1v.7M170.4 65.5v.7M170.4 67v.7M170.4 68.4v.8M170.4 69.9v.7"/>
<path d="M170.4 71.4v.7M170.4 72.8v.7M170.4 74.3v.7M170.4 75.7v.8M170.4 77.2v.7M170.4 78.7v.7M181.3 70.5h7.6M181.5 72.4h7.4M185.6 77.9h3.3M185.6 76.1h3.3M185.6 79.8h3.3M186 74.2h2.9"/>
<path d="M188.9 62.7h11.1M188.9 64.6h11.1M188.9 66.4h11.1M188.9 68.3h11.1M188.9 72h11.1M188.9 73.8h11.1M188.9 75.7h11.1M188.9 77.5h11.1M188.9 79.4h11.1M194.5 70.1h5.5M209.3 61.1v.7M209.3 62.6v.7"/>
<path d="M209.3 64.1v.7M209.3 65.5v.7M209.3 67v.7M209.3 68.4v.8M209.3 69.9v.7M209.3 71.4v.7M209.3 72.8v.7M209.3 74.3v.7M209.3 75.7v.8M209.3 77.2v.7M209.3 78.7v.7M227.8 62.7h11.2"/>
<path d="M227.8 64.6h11.2M227.8 66.4h11.2M227.8 68.3h11.2M227.8 70.1h11.2M227.8 72h11.2M227.8 73.8h11.2M227.8 75.7h11.2M227.8 77.5h11.2M227.8 79.4h11.2M7.2 86.4h2.8M62.8 81.2h5.6M62.8 83.1h5.6"/>
<path d="M62.8 84.9h5.6M62.8 86.8h5.6M62.8 88.6h5.6M62.8 90.5h5.6M62.8 92.4h5.6M62.8 94.2h5.6M62.8 96.1h5.6M62.8 97.9h5.6M62.8 99.8h5.6M70.3 87.2h4.1M70.3 89.1h2.7M70.3 90.9h2.8"/>
<path d="M90.6 81.2h5.6M90.6 83.1h5.6M90.6 84.9h5.6M90.6 86.8h5.6M90.6 88.6h5.6M90.6 90.5h5.6M90.6 92.4h5.6M90.6 94.2h5.6M90.6 96.1h5.6M90.6 97.9h5.6M98.1 94.6h3.5M98.1 96.5h6.7"/>
<path d="M112.9 97.9l-1.9 1.9h-20.4M112.9 99.8l-1.9 1.8h-20.4M145.5 94.6h4.5M145.7 83.5h4.3M145.7 85.4h4.3M145.7 87.2h4.3M145.7 89.1h4.3M145.7 92.8h4.3M150 81.2h11.1M150 83.1h11.1M150 84.9h11.1M150 86.8h11.1"/>
<path d="M150 88.6h11.1M150 90.5h11.1M150 92.4h11.1M150 94.2h11.1M150 96.1h11.1M150 97.9h11.1M150 99.8h11.1M170.4 80.1v.7M170.4 81.6v.7M170.4 83v.8M170.4 84.5v.7M170.4 86v.7"/>
<path d="M170.4 87.4v.7M170.4 88.9v.7M170.4 90.3v.8M170.4 91.8v.7M170.4 93.3v.7M170.4 94.7v.7M170.4 96.2v.7M170.4 97.6v.8M170.4 99.1v.7M185.2 81.6h3.7M188.9 81.2h11.1M188.9 83.1h11.1"/>
<path d="M188.9 84.9h11.1M188.9 86.8h11.1M188.9 88.6h11.1M188.9 90.5h11.1M188.9 92.4h11.1M188.9 94.2h11.1M188.9 96.1h11.1M188.9 97.9h11.1M194.5 99.8h5.5M209.3 80.1v.7M209.3 81.6v.7M209.3 83v.8"/>
<path d="M209.3 84.5v.7M209.3 86v.7M209.3 87.4v.7M209.3 88.9v.7M209.3 90.3v.8M209.3 91.8v.7M209.3 93.3v.7M209.3 94.7v.7M209.3 96.2v.7M209.3 97.6v.8M209.3 99.1v.7M223.6 83.5h4.2"/>
<path d="M223.6 94.6h4.2M223.6 92.8h4.2M223.6 96.5h4.2M225.9 85.4h1.9M226.1 89.1h1.7M226.5 87.2h1.3M227.8 81.2h11.2M227.8 83.1h11.2M227.8 84.9h11.2M227.8 86.8h11.2M227.8 88.6h11.2M227.8 90.5h11.2"/>
<path d="M227.8 92.4h11.2M227.8 94.2h11.2M227.8 96.1h11.2M227.8 97.9h11.2M227.8 99.8h11.2M287.2 86.4h2.7M62.8 101.6h5.6M62.8 103.5h5.6M62.8 105.3h5.6M62.8 107.2h5.6M62.8 109h5.6M62.8 110.9h5.6"/>
<path d="M62.8 112.8h5.6M62.8 114.6h5.6M62.8 116.5h5.6M62.8 118.3h5.6M112.9 101.6l-1.9 1.9h-20.4M112.9 103.5l-1.9 1.8h-20.4M112.9 105.3l-1.9 1.9h-20.4M112.9 107.2l-1.9 1.8h-20.4M112.9 109l-1.9 1.9h-20.4M112.9 110.9l-1.9 1.9h-20.4M112.9 112.8l-1.9 1.8h-20.4M112.9 114.6l-1.9 1.9h-20.4"/>
<path d="M112.9 116.5l-1.9 1.8h-20.4M112.9 118.3l-1.9 1.9h-20.4M142.8 111.3h7.2M145.5 115h4.5M150 101.6h11.1M150 103.5h11.1M150 105.3h11.1M150 107.2h11.1M150 109h11.1M150 110.9h11.1M150 112.8h11.1M150 114.6h11.1"/>
<path d="M150 116.5h11.1M150 118.3h11.1M170.4 100.6v.7M170.4 102v.7M170.4 103.5v.7M170.4 104.9v.8M170.4 106.4v.7M170.4 107.9v.7M170.4 109.3v.7M170.4 110.8v.7M170.4 112.2v.8M170.4 113.7v.7"/>
<path d="M170.4 115.2v.7M170.4 116.6v.7M170.4 118.1v.7M170.4 119.5v.8M179.8 107.6h9.1M179.8 105.7h9.1M179.8 103.9h9.1M180.3 100.2h8.6M185.8 109.5h3.1M188.9 101.6h11.1M188.9 105.3h11.1M188.9 107.2h11.1"/>
<path d="M188.9 109h11.1M188.9 110.9h11.1M188.9 112.8h11.1M188.9 114.6h11.1M188.9 116.5h11.1M188.9 118.3h11.1M194.5 103.5h5.5M209.3 100.6v.7M209.3 102v.7M209.3 103.5v.7M209.3 104.9v.8M209.3 106.4v.7"/>
<path d="M209.3 107.9v.7M209.3 109.3v.7M209.3 110.8v.7M209.3 112.2v.8M209.3 113.7v.7M209.3 115.2v.7M209.3 116.6v.7M209.3 118.1v.7M209.3 119.5v.8M221.8 115h6M224.6 113.2h3.2M227.8 101.6h11.2"/>
<path d="M227.8 103.5h11.2M227.8 105.3h11.2M227.8 107.2h11.2M227.8 109h11.2M227.8 110.9h11.2M227.8 112.8h11.2M227.8 114.6h11.2M227.8 116.5h11.2M227.8 118.3h11.2M7.2 123.3h2.8M62.8 120.2h5.6M62.8 122h5.6"/>
<path d="M62.8 123.9h5.6M62.8 125.7h5.6M62.8 127.6h5.6M62.8 129.4h5.6M62.8 131.3h5.6M62.8 133.1h5.6M62.8 135h5.6M70.3 133.6h3.8M70.3 131.7h5.9M90.6 129.4h5.6M90.6 131.3h5.6M90.6 133.1h5.6"/>
<path d="M90.6 135h5.6M112.9 120.2l-1.9 1.8h-20.4M112.9 122l-1.9 1.9h-20.4M112.9 123.9l-1.9 1.8h-20.4M112.9 125.7l-1.9 1.9h-20.4M150 120.2h11.1M170.4 126.9v.7h.7M170.4 121v.7M170.4 122.5v.7M170.4 123.9v.8M170.4 125.4v.7M171.8 127.6h.8"/>
<path d="M173.3 127.6h.7M174.8 127.6h.7M176.2 127.6h.8M177.7 127.6h.8M179.2 127.6h.7M180.7 127.6h.7M182.1 127.6h.8M183.6 127.6h.7M185.1 127.6h.7M186.5 127.6h.8M188 127.6h.7M188.9 120.2h11.1"/>
<path d="M189.5 127.6h.7M190.9 127.6h.8M192.4 127.6h.7M193.9 127.6h.7M195.3 127.6h.8M196.8 127.6h.7M198.3 127.6h.7M199.7 127.6h.8M201.2 127.6h.8M202.7 127.6h.7M204.2 127.6h.7M205.6 127.6h.8"/>
<path d="M207.1 127.6h.7M209.3 126.9v.7h-.7M209.3 121v.7M209.3 122.5v.7M209.3 123.9v.8M209.3 125.4v.7M227.8 120.2h11.2M287.2 123.3h2.7M131.4 144.3v5.5M131.4 151.7v5.5M138.9 144.3v5.5M138.9 151.7v5.5"/>
<path d="M152.7 157.6h3.3M202.8 157.6h5.9M7.2 160.2h2.8M10.9 175.8h35.2v20.4h-35.2zM14.3 179.5h.7M14.6 179.1v.8M42.1 179.5h.7M42.4 179.1v.8M287.2 160.2h2.7M14.3 190.6h.7M14.6 190.2v.8M42.1 190.6h.7"/>
<path d="M42.4 190.2v.8M44.6 197.1v2.8M79.3 197.1v2.8M113.9 197.1v2.8M134.2 192.5h.3M134.2 192.4h.3M134.2 192.3h.3M134.2 192.2h.3M134.2 192.1h.3M134.2 192h.3M134.2 191.9h.3M134.2 192.6l.4 .1"/>
<path d="M134.2 192.6h.4M134.2 192.6h.3M134.2 192.7h1M134.3 191.6l.9 .1M134.3 191.6h.8M134.3 192.8h.8M134.4 192.9h.7M134.4 191.5h.7M134.4 191.5h.6M134.5 192.9h.5M134.5 191.9h-.3M134.5 191.8l-.3 .1"/>
<path d="M134.6 193h.3M134.6 191.8h-.4M134.6 191.4h.3M134.6 191.7h-.4M134.8 191.7h.4M134.9 192.6h.4M134.9 191.8h.4M135 192.5h.3M135 192.4h.3M135 192.3h.3M135 192.2h.3M135 192.1h.3"/>
<path d="M135 192h.3M135 191.9h.3M135.2 192.7l-.9 .1M135.2 191.7h-1M135.2 192.6l-.4 .1M135.6 193.5h.1M135.6 193.4h.2M135.6 193.3h.3M135.6 193.2h.3M135.6 193.1h.3M135.6 193h.3M135.6 192.7h1"/>
<path d="M135.6 192.6l.4 .1M135.6 192.6h.4M135.6 192.6h.3M135.6 192.5h.3M135.6 192.4h.3M135.6 192.3h.3M135.6 192.2h.3M135.6 192.1h.3M135.6 192h.3M135.6 191.9h.3M135.6 191.7h1M135.7 191.7h.9"/>
<path d="M135.7 191.6h.8M135.8 191.5h.7M135.8 193.4h-.2M135.8 191.5h.6M135.9 191.8l-.3 .1M136 193h.3M136 191.8h-.4M136 191.4h.2M136 191.7h-.4M136.2 192.7h.4M136.2 191.7h.4M136.3 191.8h.3"/>
<path d="M136.3 191.8h.4M136.4 192.5h.3M136.4 191.9h.3M136.4 192.9h-.8M136.4 192.4h.3M136.4 192.3h.3M136.4 192.2h.3M136.4 192.1h.3M136.4 192h.3M136.5 192.9h-.9M136.5 192.8h-.9M136.6 192.6h-.3"/>
<path d="M136.7 192.6h-.4M137 192.6h.4M137 192.6h.3M137 192.5h.3M137 192.1h1M137 192l.3 .1M137 192h.2M137 191.9h.3M137 191.8h.3M137 192.6l.4 .1M137 192.7h1M137 191.7h1"/>
<path d="M137.1 192.7h.9M137.1 191.7h.9M137.1 192.8h.8M137.1 191.6h.8M137.2 192.9h.6M137.2 191.5h.7M137.2 191.5h.6M137.3 192h-.3M137.4 192.4h-.4M137.4 192.1h.6M137.4 191.8h-.4M137.4 193h.3"/>
<path d="M137.4 191.4h.2M137.4 191.7h-.4M137.5 192.4h-.5M137.5 192h.5M137.6 192.3h-.6M137.6 192h.4M137.6 191.7h.4M137.7 191.8h.3M137.7 192.6h.3M137.7 191.9h.3M137.7 192.5h.3M137.8 192.5h.2"/>
<path d="M137.8 192.4h.2M137.8 192.2l-.8 .1M137.9 192.2h-.9M137.9 192.3h.1M138 192.3h.1M138 192.6l-.4 .1M138.4 192.9h.2M138.4 192.8h.3M138.4 192.7h.3M138.4 192.6h.3M138.4 192.5h.3M138.4 192.4h.3"/>
<path d="M138.4 192.3h.3M138.4 192.2h.3M138.4 192.1h.3M138.4 192h.3M138.4 191.9h.3M138.4 193h.1M138.4 191.7h1M138.5 191.6h.9M138.5 191.6h.8M138.6 191.5h.7M138.6 191.5h.6M138.6 192.9h-.2"/>
<path d="M138.7 192.8h-.3M138.7 191.8l-.3 .1M138.8 191.8h-.4M138.8 191.4h.2M138.8 191.7h-.4M139 191.7h.4M139.1 191.8h.3M139.1 192.9h.3M139.1 192.8h.3M139.1 192.7h.3M139.1 192.6h.3M139.1 192.5h.3"/>
<path d="M139.1 192.4h.3M139.1 192.3h.3M139.1 192.2h.3M139.1 192.1h.3M139.1 192h.3M139.1 191.9h.3M139.2 193h.1M139.4 192.9h-.3M140.7 192.9h.2M140.7 192.8h.2M140.7 192.7h.2M140.7 192.6h.2"/>
<path d="M140.7 192.5h.2M140.7 192.4h.2M140.7 192.3h.2M140.7 192.2h.2M140.7 192.1h.2M140.7 192h.2M140.7 191.9h.2M140.7 191.7h.8M140.7 191.6l.8 .1M140.7 191.6h.8M140.7 191.6h.7M140.7 191.5h.2"/>
<path d="M140.7 191.4h.2M140.7 191.3h.2M140.7 191.2h.2M140.7 191.1h.2M140.8 193h-.1M140.8 191h.1M140.8 192.9h-.1M140.9 191.8l-.2 .1M141 191.5h.3M141 191.8h-.3M141.1 191.7h-.4M141.2 191.7h.4"/>
<path d="M141.3 191.8h.3M141.4 191.8l.2 .1M141.4 191.9h.2M141.4 192h.2M141.5 192.9h.1M141.5 192.8h.1M141.5 192.7h.1M141.5 192.6h.1M141.5 192.5h.1M141.5 192.4h.1M141.5 192.3h.1M141.5 192.2h.1"/>
<path d="M141.5 192.1h.1M141.5 192h.1M141.5 193h.1M141.6 192.9h-.1M141.6 192.8h-.1M142 192.7l.3 .1M142 192.7h.2M142 192.6h.2M142 192.1h.1M142 192h.2M142 191.9h.2M142 192.8h.6"/>
<path d="M142.1 192.9h.5M142.1 191.7h.8M142.1 191.6l.7 .1M142.2 191.6h.6M142.2 192l-.2 .1M142.2 192.3h.8M142.2 193h.4M142.2 191.6h.5M142.2 192.5h-.2M142.3 192.5h-.3M142.3 191.8l-.3 .1M142.3 192.2h.7"/>
<path d="M142.3 191.5h.4M142.3 191.8h-.3M142.4 192.4h-.4M142.4 193h.1M142.4 192.2h.6M142.5 192.8h.1M142.5 192.4h-.5M142.5 192.1h.5M142.6 192.1h.4M142.6 192.3h-.5M142.6 191.8h.3M142.7 191.8l.3 .1"/>
<path d="M142.7 192h.3M142.7 191.9h.3M142.7 193h.2M142.7 192.8h.3M142.7 192.7h.3M142.7 192.6h.3M142.7 192.5h.3M142.7 192.4h.3M142.7 192.3h.3M142.9 191.7h-.9M143 192.9h-.3M143 192.3h-.9"/>
<path d="M143.3 192.8h.2M143.3 192.7h.2M143.3 192.6h.2M143.3 192.5h.2M143.3 192.4h.2M143.3 192.3h.2M143.3 192.2h.2M143.3 192.1h.2M143.3 192h.2M143.3 191.9h.2M143.4 191.7h.8M143.4 193h-.1"/>
<path d="M143.5 191.6h.6M143.5 192.9h-.2M143.5 192h-.2M143.6 191.9h-.3M143.6 191.6h.5M143.6 191.8l-.3 .1M143.6 191.5h.4M143.7 191.8h-.4M143.9 191.8h.4M144 191.8h.3M144 191.9h.3M144.1 191.9h.2"/>
<path d="M144.1 192h.2M144.3 192l-.2 .1M144.6 192.6h.2M144.6 192.5h.2M144.6 192.4h.2M144.6 192.3h.2M144.6 192.2h.2M144.6 192.1h.2M144.6 192h.2M144.6 192.6h.3M144.6 191.9h.2M144.7 192.7h.2"/>
<path d="M144.7 192.6h.2M144.7 191.8h.2M144.7 192.7l.4 .1M144.7 192.8h.8M144.7 191.7h.9M144.8 191.7h.8M144.8 192.9h.7M144.8 191.6h.8M144.8 192.9h.6M144.9 191.6h.7M144.9 191.9h-.2M144.9 193h.5"/>
<path d="M144.9 191.5h.4M145 191.8h-.3M145.1 193h.1M145.2 192.8h.4M145.2 191.8h.4M145.3 191.8h.3M145.4 191.9h.2M145.4 192.6h.2M145.4 192.5h.2M145.4 192.4h.2M145.4 192.3h.2M145.4 192.2h.2"/>
<path d="M145.4 192h.2M145.4 191.5h.2M145.4 191.4h.2M145.4 191.3h.2M145.4 191.2h.2M145.4 191.1h.2M145.4 192.1h.2M145.5 191.1h.1M145.5 191h.1M145.6 192.7h-.3M145.6 192.6l-.2 .1M145.6 192.6h-.2"/>
<path d="M145.6 191.7h-.9M145.8 192.6h.2M145.8 192.5h.2M145.8 192.4h.2M145.8 192.3h.2M145.8 192.2h.2M145.8 192.1h.2M145.8 192h.2M145.8 191.9h.2M145.8 191.8h.2M145.8 191.7h.2M145.8 191.6h.2"/>
<path d="M145.8 192.7l.3 .1M145.8 192.7h.3M145.9 191.6h.1M145.9 192.9h1.1M145.9 192.9h1M146 191.5h.1M146 193h.4M146.2 193h.1M146.2 192.8h.5M146.3 192.7h.3M146.3 192.6h.3M146.3 192.6h.2"/>
<path d="M146.3 192.5h.2M146.3 192.4h.2M146.3 192.3h.2M146.3 192.2h.2M146.3 192.1h.2M146.3 192h.2M146.3 191.9h.2M146.3 191.8h.2M146.3 191.7h.2M146.3 191.6h.2M146.4 191.6h.1M146.5 191.5h.1"/>
<path d="M146.5 193h.4M146.8 192.7h.3M146.8 192.6h.3M146.9 192.6h.2M146.9 192.5h.2M146.9 192.4h.2M146.9 192.3h.2M146.9 192.2h.2M146.9 192.1h.2M146.9 192h.2M146.9 191.9h.2M146.9 191.8h.2"/>
<path d="M146.9 191.7h.2M146.9 191.6h.2M147 191.5h.1M147 192.8h-1.1M147.1 192.7l-.4 .1M147.3 192.7h.2M147.3 192.6h.2M147.3 192.7l.3 .1M147.3 192.1h.1M147.3 192h.2M147.3 191.9h.2M147.3 192.8h.6"/>
<path d="M147.4 192.9h.5M147.4 191.7h.8M147.4 191.7h.7M147.4 192l-.1 .1M147.4 191.6h.7M147.5 192h-.2M147.5 193h.4M147.5 192.3h.8M147.5 191.6h.5M147.5 192.5h-.2M147.6 192.5h-.3M147.6 191.8l-.3 .1"/>
<path d="M147.6 192.2h.7M147.6 191.5h.3M147.6 191.8h-.3M147.7 192.4h-.4M147.7 193h.1M147.7 192.2h.6M147.7 192.8h.2M147.8 192.4h-.5M147.8 192.1h.5M147.9 192.3h-.5M147.9 192.1h.4M147.9 191.8h.3"/>
<path d="M148 191.8l.3 .1M148 191.9h.3M148 192h.3M148.1 192.9h.2M148.1 192.8h.2M148.1 192.7h.2M148.1 192.6h.2M148.1 192.5h.2M148.1 192.4h.2M148.1 192.3h.2M148.1 192h.2M148.2 193h-.1"/>
<path d="M148.2 191.7h-.8M148.3 192.9h-.2M148.3 192.3h-.9M148.6 197.1v2.8M148.6 192.9h.2M148.6 192.8h.2M148.6 192.7h.2M148.6 192.6h.2M148.6 192.5h.2M148.6 192.4h.2M148.6 192.3h.2M148.6 192.2h.2"/>
<path d="M148.6 192.1h.2M148.6 192h.2M148.6 191.9h.2M148.6 193h.1M148.7 193h-.1M148.7 191.7h.8M148.8 192.9h-.2M148.8 191.6h.6M148.8 192h-.2M148.8 191.9h-.2M148.9 191.8l-.3 .1M148.9 191.5h.4"/>
<path d="M149 191.8h-.4M149.2 191.8h.3M149.3 191.8l.3 .1M149.4 191.9h.2M149.4 192h.2M149.5 191.7h-.8M149.5 192l-.1 .1M149.6 192h-.2M149.9 192.6h.3M149.9 192.6h.2M149.9 192.5h.2M149.9 192.5h.3"/>
<path d="M149.9 192.2h.8M149.9 192.2h.3M149.9 192.2h.2M149.9 192.1h.2M149.9 192h.2M149.9 191.9h.2M149.9 192.6l.3 .1M149.9 192.7h.3M150 192.7l.3 .1M150 192.8h.8M150 191.7h.8M150.1 191.7h.7"/>
<path d="M150.1 192.9h.6M150.1 191.6h.6M150.2 191.9h-.3M150.2 191.6h.5M150.2 193h.4M150.2 191.8l-.3 .1M150.2 191.5h.4M150.3 192.4h-.4M150.3 191.8h-.3M150.4 191.7h-.4M150.4 193h.1M150.4 192.4h-.5"/>
<path d="M150.4 192.1h.5M150.4 191.7h.4M150.5 192.1h.4M150.5 192.8h.3M150.5 192.3h-.6M150.5 191.8h.4M150.6 192.3h-.7M150.6 192h.3M150.6 191.8l.3 .1M150.6 192.6h.3M150.6 191.9h.3M150.7 192.6h.2"/>
<path d="M150.7 191.9h.2M150.7 192h.2M150.7 192.5h.2M150.7 192.4h.2M150.8 192.2h-.6M150.9 192.4h.1M150.9 192.7h-.3M150.9 192.2h-.6M156.4 192.5h.4M156.4 192.5h.3M156.4 192.4h.3M156.4 192.3h.3"/>
<path d="M156.4 192.2h.3M156.4 192.1h.3M156.4 192h.3M156.4 191.9h.3M156.5 192.6l.4 .1M156.5 192.6h.3M156.5 192.7h1M156.5 192.7h.9M156.5 191.6l.9 .1M156.5 192.8h.9M156.5 191.6h.9M156.6 192.8h.8"/>
<path d="M156.6 191.6h.8M156.6 192.9h.7M156.6 191.5h.7M156.7 191.5h.6M156.7 192.9h.5M156.7 191.9h-.3M156.8 191.8l-.4 .1M156.8 193h.3M156.8 191.8h-.3M156.8 191.4h.3M156.9 191.7h-.4M157.1 191.7h.4"/>
<path d="M157.1 192.6h.4M157.1 191.8h.4M157.2 192.6h.3M157.2 191.8h.3M157.2 192.5h.3M157.2 191.9h.3M157.2 192.4h.3M157.2 192.3h.3M157.2 192.2h.3M157.2 192.1h.3M157.2 192h.3M157.4 191.7h-.9"/>
<path d="M157.5 192.6l-.4 .1M157.8 193.5h.2M157.8 193.3h.3M157.8 193.2h.3M157.8 193.1h.3M157.8 193h.3M157.8 192.7h1M157.8 192.7h1.1M157.8 192.6l.5 .1M157.8 192.6h.4M157.8 192.5h.3M157.8 192.4h.3"/>
<path d="M157.8 192.3h.3M157.8 192.2h.3M157.8 192.1h.3M157.8 192h.3M157.8 191.9h.3M157.9 191.7h1M157.9 191.7h.9M157.9 191.6h.9M158 191.6h.7M158 191.5h.7M158.1 193.4h-.3M158.1 191.5h.5"/>
<path d="M158.2 191.8l-.4 .1M158.2 193h.3M158.2 191.8h-.4M158.2 191.4h.3M158.3 191.7h-.4M158.5 192.7h.4M158.5 191.7h.4M158.5 191.8h.4M158.6 191.8h.3M158.6 192.5h.3M158.6 191.9h.3M158.6 192.4h.3"/>
<path d="M158.6 192.3h.3M158.6 192.2h.3M158.6 192.1h.3M158.6 192h.3M158.6 192.9h-.8M158.7 192.9h-.9M158.7 192.8h-.9M158.8 192.8h-1M158.9 192.6h-.4M158.9 192.6h-.3M159.2 192.6h.4M159.2 192.5h.3"/>
<path d="M159.2 192.1h1.1M159.2 192l.3 .1M159.2 192h.3M159.2 191.9h.3M159.2 191.8h.4M159.3 192.6l.4 .1M159.3 192.7h.9M159.3 191.7h1M159.3 191.7h.9M159.3 192.8h.9M159.3 191.6h.9M159.4 192.8h.7"/>
<path d="M159.4 191.6h.7M159.4 192.9h.7M159.4 191.5h.7M159.5 191.5h.6M159.5 192.9h.5M159.5 192h-.3M159.6 192.4h-.4M159.6 192.1h.7M159.6 191.8h-.4M159.6 193h.3M159.6 191.4h.3M159.7 191.7h-.4"/>
<path d="M159.7 192.4h-.5M159.7 192h.6M159.8 192.3h-.6M159.9 192h.4M159.9 191.7h.4M159.9 192.3h-.7M159.9 191.8h.4M159.9 192.6h.4M160 191.9h.3M160 192.6h.3M160 192.5h.3M160 191.8h.3"/>
<path d="M160 192.4h.3M160 192.2l-.8 .1M160.1 192.2h-.9M160.1 192.3h.2M160.2 192.2h-1M160.2 192.3h.1M160.3 192.6l-.4 .1M160.6 192.9h.2M160.6 192.8h.3M160.6 192.7h.3M160.6 192.6h.3M160.6 192.5h.3"/>
<path d="M160.6 192.4h.3M160.6 192.3h.3M160.6 192.2h.3M160.6 192.1h.3M160.6 192h.3M160.6 191.9h.3M160.6 191.9h.4M160.7 193h.1M160.7 191.7h.9M160.7 191.6l.9 .1M160.7 191.6h.9M160.8 191.6h.7"/>
<path d="M160.8 191.5h.7M160.9 191.5h.5M160.9 192.9h-.3M160.9 192.8h-.3M161 191.8h-.3M161 191.4h.3M161.1 191.7h-.4M161.3 191.7h.3M161.3 191.8h.4M161.4 191.8h.3M161.4 192.9h.2M161.4 192.8h.3"/>
<path d="M161.4 192.7h.3M161.4 192.6h.3M161.4 192.5h.3M161.4 192.4h.3M161.4 192.3h.3M161.4 192.2h.3M161.4 192.1h.3M161.4 192h.3M161.4 191.9h.3M161.4 193h.1M161.7 192.9h-.3M162.9 192.9h.2"/>
<path d="M162.9 192.8h.2M162.9 192.7h.2M162.9 192.6h.2M162.9 192.5h.2M162.9 192.4h.2M162.9 192.3h.2M162.9 192.2h.2M162.9 192.1h.2M162.9 192h.2M162.9 191.9h.2M162.9 191.9h.3M162.9 191.7h.9"/>
<path d="M162.9 191.6l.9 .1M162.9 191.6h.8M162.9 191.6h.7M162.9 191.5h.2M162.9 191.4h.2M162.9 191.3h.2M162.9 191.2h.2M162.9 191.1h.2M163 193h-.1M163 191h.1M163.1 192.9h-.2M163.2 191.8l-.3 .1"/>
<path d="M163.2 191.5h.4M163.3 191.8h-.4M163.4 191.7h-.5M163.4 191.7h.4M163.5 191.8h.4M163.6 191.8h.3M163.6 191.9h.3M163.7 191.9h.2M163.7 192h.2M163.7 192.9h.2M163.7 192.8h.2M163.7 192.7h.2"/>
<path d="M163.7 192.6h.2M163.7 192.5h.2M163.7 192.4h.2M163.7 192.3h.2M163.7 192.2h.2M163.7 192.1h.2M163.8 193h-.1M163.9 192.9h-.2M163.9 192.8h-.2M164.2 192.7l.4 .1M164.2 192.7h.3M164.2 192.6l.3 .1"/>
<path d="M164.2 192.6h.2M164.2 192.5h.3M164.2 192.1h.1M164.2 192h.2M164.2 191.9h.3M164.3 192.8h.5M164.3 192.8h.6M164.3 192.9h.6M164.3 191.7h.8M164.4 192.9h.5M164.4 191.6l.7 .1M164.4 191.6h.6"/>
<path d="M164.4 192l-.2 .1M164.5 193h.4M164.5 192.3h.7M164.5 191.6h.5M164.5 192.5h-.3M164.5 191.8l-.2 .1M164.5 192.2h.7M164.5 191.5h.4M164.6 191.8h-.3M164.6 192.4h-.4M164.7 192.2h.5M164.7 193h.1"/>
<path d="M164.7 192.8h.1M164.8 192.4h-.5M164.8 192.1h.4M164.8 192.3h-.5M164.8 191.8h.4M164.9 191.8l.3 .1M165 192h.2M165 191.9h.2M165 193h.1M165 192.8h.2M165 192.7h.2M165 192.6h.2"/>
<path d="M165 192.5h.2M165 192.4h.2M165 192.3h.2M165.1 191.7h-.8M165.2 192.9h-.2M165.2 192.3h-.8M165.5 192.8h.3M165.5 192.7h.3M165.5 192.6h.3M165.5 192.5h.3M165.5 192.4h.3M165.5 192.3h.3"/>
<path d="M165.5 192.2h.3M165.5 192.1h.3M165.5 192h.3M165.5 191.9h.3M165.6 191.7h.9M165.7 193h-.2M165.7 191.7h.8M165.7 191.7h.7M165.7 192.9h-.2M165.7 191.6h.7M165.8 192.9h-.3M165.8 192h-.3"/>
<path d="M165.8 191.9h-.3M165.8 191.6h.5M165.8 191.8l-.2 .1M165.9 191.5h.3M165.9 191.8h-.3M166.2 191.8h.3M166.3 191.8h.2M166.3 191.9h.2M166.3 192h.2M166.5 192l-.2 .1M166.9 192.6h.2M166.9 192.5h.2"/>
<path d="M166.9 192.4h.2M166.9 192.3h.2M166.9 192.2h.2M166.9 192.1h.2M166.9 192h.2M166.9 191.9h.2M166.9 192.7h.3M166.9 192.7l.4 .1M167 192.8h.8M167 191.7h.9M167 192.8h.7M167 192.9h.7"/>
<path d="M167 191.6h.9M167.1 192.9h.6M167.1 191.6h.8M167.1 191.9h-.2M167.2 193h.4M167.2 191.8l-.3 .1M167.2 191.5h.3M167.2 191.8h-.3M167.3 193h.1M167.4 193h.1M167.4 192.8h.4M167.5 191.8h.4"/>
<path d="M167.5 192.7h.3M167.6 191.8h.3M167.6 191.9h.3M167.6 192.6h.3M167.6 192.5h.3M167.6 192.4h.3M167.6 192.3h.3M167.6 192.2h.3M167.6 192h.3M167.6 191.5h.3M167.6 191.4h.3M167.6 191.3h.3"/>
<path d="M167.6 191.2h.3M167.6 191.1h.3M167.7 192.1h.2M167.7 191.2h.2M167.7 191.1h.2M167.8 191h.1M167.9 192.6l-.3 .1M167.9 192.6h-.3M167.9 191.7h-1M168.1 192.6h.2M168.1 192.5h.2M168.1 192.4h.2"/>
<path d="M168.1 192.3h.2M168.1 192.2h.2M168.1 192.1h.2M168.1 192h.2M168.1 191.9h.2M168.1 191.8h.2M168.1 191.7h.2M168.1 191.6h.2M168.1 192.7l.3 .1M168.1 192.7h.2M168.1 192.8h1.2M168.1 192.8h1.1"/>
<path d="M168.1 192.9h1.1M168.2 192.9h1M168.2 191.5h.1M168.3 193h.3M168.5 192.8h.4M168.5 193h.1M168.6 192.7h.2M168.6 192.6h.2M168.6 192.5h.2M168.6 192.4h.2M168.6 192.3h.2M168.6 192.2h.2"/>
<path d="M168.6 192.1h.2M168.6 192h.2M168.6 191.9h.2M168.6 191.8h.2M168.6 191.7h.2M168.6 191.6h.2M168.7 191.5h.1M168.8 193h.3M169.1 192.7h.2M169.1 192.6h.2M169.1 192.5h.2M169.1 192.4h.2"/>
<path d="M169.1 192.3h.2M169.1 192.2h.2M169.1 192.1h.2M169.1 192h.2M169.1 191.9h.2M169.1 191.8h.2M169.1 191.7h.2M169.1 191.6h.2M169.2 191.6h.1M169.2 191.5h.1M169.3 192.7l-.3 .1M169.5 192.7h.3"/>
<path d="M169.5 192.6h.2M169.5 192.1h.1M169.5 192h.2M169.5 191.9h.2M169.5 192.8h.6M169.5 192.7l.4 .1M169.5 191.9h.3M169.6 192.8h.6M169.6 192.9h.6M169.6 191.7h.8M169.7 191.7h.7M169.7 192l-.2 .1"/>
<path d="M169.7 191.6h.6M169.7 192h-.2M169.8 193h.4M169.8 192.3h.7M169.8 191.6h.5M169.8 192.5h-.3M169.8 191.8l-.3 .1M169.8 192.2h.7M169.8 191.5h.4M169.9 191.8h-.3M169.9 192.4h-.4M169.9 192.2h.6"/>
<path d="M169.9 193h.1M170 192.8h.1M170 193h.1M170.1 192.4h-.5M170.1 192.1h.4M170.1 192.3h-.5M170.1 191.8h.4M170.2 192.9h-.5M170.2 191.8l.3 .1M170.3 191.9h.2M170.3 192h.2M170.3 192.9h.2"/>
<path d="M170.3 192.8h.2M170.3 192.7h.2M170.3 192.6h.2M170.3 192.5h.2M170.3 192.4h.2M170.3 192.3h.2M170.4 193h-.1M170.4 191.7h-.8M170.5 192.9h-.2M170.5 192.3h-.8M170.8 192.9h.2M170.8 192.8h.2"/>
<path d="M170.8 192.7h.2M170.8 192.6h.2M170.8 192.5h.2M170.8 192.4h.2M170.8 192.3h.2M170.8 192.2h.2M170.8 192.1h.2M170.8 192h.2M170.9 191.9h.2M170.9 193h.1M170.9 193h-.1M170.9 191.7h.8"/>
<path d="M171 191.7h.7M171 192.9h-.2M171 191.6h.7M171 192h-.2M171.1 191.9h-.2M171.1 191.6h.5M171.1 191.8l-.2 .1M171.2 191.5h.3M171.2 191.8h-.3M171.5 191.8h.3M171.6 191.8l.2 .1M171.6 191.9h.2"/>
<path d="M171.6 192h.2M171.8 191.7h-.9M171.8 192l-.2 .1M171.8 192h-.2M172.1 192.6h.3M172.1 192.5h.3M172.1 192.2h.9M172.1 192.2h.3M172.1 192.1h.3M172.1 192h.3M172.1 191.9h.3M172.2 192.6l.2 .1"/>
<path d="M172.2 192.7h.3M172.2 192.7l.4 .1M172.2 192.8h.9M172.3 191.7h.8M172.3 192.8h.7M172.3 191.7h.7M172.3 192.9h.7M172.3 191.6h.7M172.4 192.9h.6M172.4 191.9h-.2M172.4 191.6h.5M172.4 193h.5"/>
<path d="M172.4 191.8l-.2 .1M172.5 191.5h.3M172.5 192.4h-.4M172.5 191.8h-.3M172.6 191.7h-.4M172.6 193h.1M172.7 192.4h-.6M172.7 192.1h.4M172.7 191.7h.4M172.7 192.1h.5M172.7 192.8h.4M172.7 192.3h-.6"/>
<path d="M172.8 191.8h.3M172.8 192.3h-.7M172.9 192h.3M172.9 191.8l.2 .1M172.9 192.6h.2M172.9 191.9h.2M173 192.5h.2M173 192.4h.2M173.1 192.2h-.6M173.1 192.4h.1M173.1 192.7h-.3M173.1 192.2h-.5"/>
<path d="M183.2 197.1v2.8M217.9 197.1v2.8M252.5 197.1v2.8M287.2 197h.1"/>
<circle cx="14.6" cy="179.5" r="1.48"/>
<circle cx="14.6" cy="179.5" r=".38"/>
<circle cx="42.4" cy="179.5" r="1.48"/>
<circle cx="42.4" cy="179.5" r=".38"/>
<circle cx="14.6" cy="190.6" r="1.48"/>
<circle cx="14.6" cy="190.6" r=".38"/>
<circle cx="42.4" cy="190.6" r="1.48"/>
<circle cx="42.4" cy="190.6" r=".38"/>
</g>
<path d="M160.2 60.8h3.7v61.2h-3.7zM199.1 60.8h3.7v61.2h-3.7zM238 60.8h3.7v61.2h-3.7z" fill="none" stroke="#000" stroke-width=".32"/>
<g fill="none" stroke="#000" stroke-width=".47">
<path d="M10 12.6h277.2v184.5h-277.2zM161.1 79.4h.9M161.1 77.5h.9M161.1 75.7h.9M161.1 73.8h.9M161.1 72h.9M161.1 70.1h.9M161.1 68.3h.9M161.1 66.4h.9M161.1 64.6h.9M161.1 62.7h.9M200 79.4h1"/>
<path d="M200 77.5h1M200 75.7h1M200 73.8h1M200 72h1M200 70.1h1M200 68.3h1M200 66.4h1M200 64.6h1M200 62.7h1M239 79.4h.9M239 77.5h.9M239 75.7h.9"/>
<path d="M239 73.8h.9M239 72h.9M239 70.1h.9M239 68.3h.9M239 66.4h.9M239 64.6h.9M239 62.7h.9M161.1 99.8h.9M161.1 97.9h.9M161.1 96.1h.9M161.1 94.2h.9M161.1 92.4h.9"/>
<path d="M161.1 90.5h.9M161.1 88.6h.9M161.1 86.8h.9M161.1 84.9h.9M161.1 83.1h.9M161.1 81.2h.9M200 99.8h1M200 97.9h1M200 96.1h1M200 94.2h1M200 92.4h1M200 90.5h1"/>
<path d="M200 88.6h1M200 86.8h1M200 84.9h1M200 83.1h1M200 81.2h1M239 99.8h.9M239 97.9h.9M239 96.1h.9M239 94.2h.9M239 92.4h.9M239 90.5h.9M239 88.6h.9"/>
<path d="M239 86.8h.9M239 84.9h.9M239 83.1h.9M239 81.2h.9M161.1 118.3h.9M161.1 116.5h.9M161.1 114.6h.9M161.1 112.8h.9M161.1 110.9h.9M161.1 109h.9M161.1 107.2h.9M161.1 105.3h.9"/>
<path d="M161.1 103.5h.9M161.1 101.6h.9M200 118.3h1M200 116.5h1M200 114.6h1M200 112.8h1M200 110.9h1M200 109h1M200 107.2h1M200 105.3h1M200 103.5h1M200 101.6h1"/>
<path d="M239 118.3h.9M239 116.5h.9M239 114.6h.9M239 112.8h.9M239 110.9h.9M239 109h.9M239 107.2h.9M239 105.3h.9M239 103.5h.9M239 101.6h.9M161.1 120.2h.9M200 120.2h1"/>
<path d="M239 120.2h.9M224.1 174.9v22.2M287.2 174.9h-85.3v22.2"/>
</g>
<path d="M130 157.2h2.8M130.3 149.8h2.2v.7h-2.2zM130.5 145.6l.9-1.3 1 1.3M137.5 157.2h2.7M137.7 149.8h2.3v.7h-2.3zM137.9 145.6l1-1.3 .9 1.3M224.1 178.6h63.1M224.1 182.3h63.1M224.1 186h63.1M224.1 189.7h63.1M266.8 186v3.7M287.2 192.5v.9h-63.1" fill="none" stroke="#000" stroke-width=".19"/>
<path d="M7.2 9.9h282.7v190h-282.7z" fill="none" stroke="#000" stroke-width=".23"/>
<g fill="#000" stroke="#000" stroke-width=".18">
<path d="M61 62.5h2v.4h-2zM61 64.4h2v.3h-2zM61 66.2h2v.4h-2zM61 68.1h2v.4h-2zM61 69.9h2v.4h-2zM61 71.8h2v.4h-2zM61 73.6h2v.4h-2zM61 75.5h2v.4h-2zM61 77.3h2v.4h-2zM61 79.2h2v.4h-2zM88.8 62.5h2v.4h-2zM88.8 64.4h2v.3h-2z"/>
<path d="M88.8 66.2h2v.4h-2zM88.8 68.1h2v.4h-2zM88.8 69.9h2v.4h-2zM88.8 71.8h2v.4h-2zM88.8 73.6h2v.4h-2zM88.8 75.5h2v.4h-2zM88.8 77.3h2v.4h-2zM88.8 79.2h2v.4h-2zM61 81h2v.4h-2zM61 82.9h2v.4h-2zM61 84.8h2v.3h-2zM61 86.6h2v.4h-2z"/>
<path d="M61 88.5h2v.3h-2zM61 90.3h2v.4h-2zM61 92.2h2v.3h-2zM61 94h2v.4h-2zM61 95.9h2v.3h-2zM61 97.7h2v.4h-2zM61 99.6h2v.4h-2zM88.8 81h2v.4h-2zM88.8 82.9h2v.4h-2zM88.8 84.8h2v.3h-2zM88.8 86.6h2v.4h-2zM88.8 88.5h2v.3h-2z"/>
<path d="M88.8 90.3h2v.4h-2zM88.8 92.2h2v.3h-2zM88.8 94h2v.4h-2zM88.8 95.9h2v.3h-2zM88.8 97.7h2v.4h-2zM88.8 99.6h2v.4h-2zM61 101.4h2v.4h-2zM61 103.3h2v.4h-2zM61 105.1h2v.4h-2zM61 107h2v.4h-2zM61 108.8h2v.4h-2zM61 110.7h2v.4h-2z"/>
<path d="M61 112.6h2v.3h-2zM61 114.4h2v.4h-2zM61 116.3h2v.3h-2zM61 118.1h2v.4h-2zM61 120h2v.4h-2zM88.8 101.4h2v.4h-2zM88.8 103.3h2v.4h-2zM88.8 105.1h2v.4h-2zM88.8 107h2v.4h-2zM88.8 108.8h2v.4h-2zM88.8 110.7h2v.4h-2zM88.8 112.6h2v.3h-2z"/>
<path d="M88.8 114.4h2v.4h-2zM88.8 116.3h2v.3h-2zM88.8 118.1h2v.4h-2zM88.8 120h2v.4h-2zM61 121.8h2v.4h-2zM61 123.7h2v.4h-2zM61 125.5h2v.4h-2zM61 127.4h2v.4h-2zM61 129.2h2v.4h-2zM61 131.1h2v.4h-2zM61 132.9h2v.4h-2zM61 134.8h2v.4h-2z"/>
<path d="M88.8 121.8h2v.4h-2zM88.8 123.7h2v.4h-2zM88.8 125.5h2v.4h-2zM88.8 127.4h2v.4h-2zM88.8 129.2h2v.4h-2zM88.8 131.1h2v.4h-2zM88.8 132.9h2v.4h-2zM88.8 134.8h2v.4h-2zM130.2 151h2.4v.7h-2.4zM137.6 151h2.5v.7h-2.5z"/>
</g>
<g fill="none" stroke="#000" stroke-width=".3">
<path d="M138.4 187.3h2.9M138.4 187.1h2.9M138.4 186.8h2.9M138.4 186.6h2.9M139 186.3h2.4M139.3 184.4h1.6M139.3 189.5h1.5M139.4 189.3h2.2M139.5 184.6h6.1M139.5 184.1h1.1M139.6 189.8h.9M139.6 189h2.1"/>
<path d="M139.7 184.8h5.7M139.7 183.9h.6M139.8 187.6h1.6M139.8 186.1h1.7M139.8 190h.4M139.8 188.8h2M139.8 187.8h1.8M139.9 185.8h1.9M139.9 185.1h5.3M139.9 188h2.1M140 183.6h.1M140 183.6l1 .9 .9-.4 .1-1.3h1.1l.1 1.3"/>
<path d="M140 183.6l-.7 .7 .8 1.1-.3 .8-1.4 .2v1l1.4 .1v.4M140 185.6h5.1M140 188.6h1.9M140.1 188.3h1.9M140.1 185.3h4.9M141.2 184.4h2.7M141.4 189.5h.1M141.9 184.1h1.3M141.9 183.9h1.3M142 183.6h1.2M142 183.4h1.1M142 183.1h1.1"/>
<path d="M142 182.9h1.1M142.5 185.6a1.3 1.3 0 0 0-1.2 1.1 1.3 1.3 0 0 0 .7 1.4l-.5 1.4-.5-.2-1 .9-.7-.7 .8-1.1-.3-.5M142.7 185.6l.6 .2M143.1 188.3h2M143.2 188h2M143.2 188.6h1.9M143.3 185.8a1.31 1.31 0 0 1-.3 2.3l.7 1.4 .4-.2 1 .9 .7-.7-.8-1.1 .3-.5M143.3 185.8h1.9M143.3 188.8h2M143.4 189h2.1M143.5 187.8h1.8M143.6 189.3h2.1"/>
<path d="M143.6 186.1h1.7M143.6 189.5h.1M143.7 187.6h1.7M143.7 186.3h2.4M143.8 187.3h2.9M143.8 186.6h2.9M143.8 187.1h2.9M143.8 186.8h2.9M144.2 184.4h1.6M144.3 189.5h1.5M144.5 184.1h1.1M144.6 189.8h.9"/>
<path d="M144.8 183.9h.6M144.9 190h.4M145.1 183.6l.7 .7-.8 1.1 .4 .8 1.3 .2v1l-1.3 .1-.1 .4M145.1 183.6l-1 .9-.9-.4M145.1 183.6h.1M160.7 187.3h2.9M160.7 187.1h2.8M160.7 186.8h2.8M160.7 186.6h2.9M161.3 186.3h2.3M161.5 184.4h1.7M161.6 189.5h1.4"/>
<path d="M161.7 189.3h2.1M161.7 184.6h6.2M161.7 184.1h1.2M161.8 189.8h.9M161.9 189h2M161.9 184.8h5.8M162 183.9h.5M162 187.6h1.7M162.1 186.1h1.7M162.1 190h.3M162.1 188.8h1.9M162.1 187.8h1.8"/>
<path d="M162.1 185.8h2M162.1 185.1h5.4M162.2 188h2M162.2 183.6h.1M162.2 183.6l1.1 .9 .8-.4M162.2 183.6l-.7 .7 .9 1.1-.4 .8-1.3 .2v1l1.3 .1 .1 .4M162.3 185.6h5M162.3 188.6h1.8M162.3 188.3h1.9M162.3 185.3h5M163.5 184.4h2.6M163.7 189.5h.1"/>
<path d="M164.1 184.1h1.4M164.1 184.1l.2-1.3h1l.1 1.3M164.2 183.9h1.2M164.2 183.6h1.2M164.2 183.4h1.2M164.3 183.1h1.1M164.3 182.9h1M164.7 185.6a1.3 1.3 0 0 0-1.2 1.1 1.3 1.3 0 0 0 .8 1.4l-.6 1.4-.4-.2-1.1 .9-.7-.7 .9-1.1-.3-.5M164.9 185.6l.6 .2M165.4 188.3h1.9M165.4 188h2M165.5 188.6h1.8"/>
<path d="M165.5 185.8a1.29 1.29 0 0 1-.2 2.3l.6 1.4 .4-.2 1.1 .9 .7-.7-.9-1.1 .3-.5M165.5 185.8h2M165.6 188.8h1.9M165.7 189h2M165.7 187.8h1.8M165.8 189.3h2.1M165.8 186.1h1.8M165.9 189.5h.1M165.9 187.6h1.7M166 186.3h2.3M166 187.3h3M166.1 186.6h2.9"/>
<path d="M166.1 187.1h2.9M166.1 186.8h2.9M166.5 184.4h1.6M166.6 189.5h1.4M166.8 184.1h1.1M166.9 189.8h.9M167.1 183.9h.5M167.2 190h.3M167.4 183.6h.1M167.4 183.6l.7 .7-.9 1.1 .4 .8 1.4 .2v1l-1.4 .1-.1 .4M167.4 183.6l-1.1 .9-.9-.4"/>
</g>
<g fill="#000" stroke="#000" stroke-width=".18">
<path d="M13.1 179.5h1.2l.1 .2 .2 .2v1.1a1.48 1.48 0 0 1-1.5-1.5z" fill-rule="evenodd"/>
<path d="M14.6 178a1.45 1.45 0 0 1 1.5 1.5h-1.1l-.1-.3-.3-.1z" fill-rule="evenodd"/>
<path d="M41.4 178.4l.6-.3 .4-.1v1.1l-.2 .1-.1 .3h-1.1v-.5z" fill-rule="evenodd"/>
<path d="M42.4 179.9l.3-.2 .1-.2h1.1a1.48 1.48 0 0 1-1.5 1.5z" fill-rule="evenodd"/>
<path d="M13.1 190.6h1.2l.1 .3 .2 .1v1.1a1.45 1.45 0 0 1-1.5-1.5z" fill-rule="evenodd"/>
<path d="M14.6 189.1a1.45 1.45 0 0 1 1.5 1.5h-1.1l-.1-.2-.3-.2z" fill-rule="evenodd"/>
<path d="M41.4 189.5l.6-.3 .4-.1v1.1l-.2 .2-.1 .2h-1.1v-.5z" fill-rule="evenodd"/>
<path d="M42.4 191l.3-.1 .1-.3h1.1a1.45 1.45 0 0 1-1.5 1.5z" fill-rule="evenodd"/>
</g>
<path d="M118.4 90.5h-3.7l-1.8 1.9v33.3" fill="none" stroke="#000" stroke-width=".57"/>
<use href="#words"/>
</svg>
